VERSION 5.8 ;
BUSBITCHARS "[]" ;
DIVIDERCHAR "/" ;
UNITS
    DATABASE MICRONS 1000 ;
END UNITS

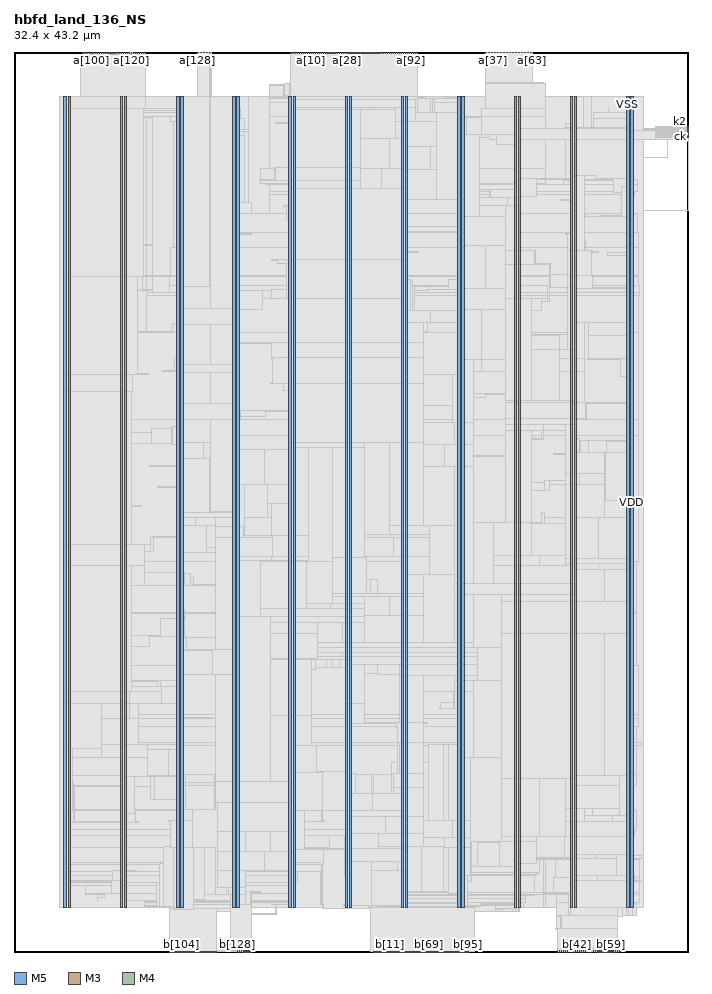
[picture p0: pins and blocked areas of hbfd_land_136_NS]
MACRO hbfd_land_136_NS
  FOREIGN hbfd_land_136_NS 0 0 ;
  CLASS BLOCK ;
  SIZE 32.4 BY 43.2 ;
  PIN a[0]
    DIRECTION INPUT ;
    USE SIGNAL ;
    PORT
      LAYER M5 ;
        RECT  13.296 43.116 13.32 43.2 ;
    END
  END a[0]
  PIN a[100]
    DIRECTION INPUT ;
    USE SIGNAL ;
    PORT
      LAYER M5 ;
        RECT  3.696 43.116 3.72 43.2 ;
    END
  END a[100]
  PIN a[101]
    DIRECTION INPUT ;
    USE SIGNAL ;
    PORT
      LAYER M5 ;
        RECT  3.792 43.116 3.816 43.2 ;
    END
  END a[101]
  PIN a[102]
    DIRECTION INPUT ;
    USE SIGNAL ;
    PORT
      LAYER M5 ;
        RECT  3.888 43.116 3.912 43.2 ;
    END
  END a[102]
  PIN a[103]
    DIRECTION INPUT ;
    USE SIGNAL ;
    PORT
      LAYER M5 ;
        RECT  3.984 43.116 4.008 43.2 ;
    END
  END a[103]
  PIN a[104]
    DIRECTION INPUT ;
    USE SIGNAL ;
    PORT
      LAYER M5 ;
        RECT  4.08 43.116 4.104 43.2 ;
    END
  END a[104]
  PIN a[105]
    DIRECTION INPUT ;
    USE SIGNAL ;
    PORT
      LAYER M5 ;
        RECT  4.176 43.116 4.2 43.2 ;
    END
  END a[105]
  PIN a[106]
    DIRECTION INPUT ;
    USE SIGNAL ;
    PORT
      LAYER M5 ;
        RECT  4.272 43.116 4.296 43.2 ;
    END
  END a[106]
  PIN a[107]
    DIRECTION INPUT ;
    USE SIGNAL ;
    PORT
      LAYER M5 ;
        RECT  4.368 43.116 4.392 43.2 ;
    END
  END a[107]
  PIN a[108]
    DIRECTION INPUT ;
    USE SIGNAL ;
    PORT
      LAYER M5 ;
        RECT  4.464 43.116 4.488 43.2 ;
    END
  END a[108]
  PIN a[109]
    DIRECTION INPUT ;
    USE SIGNAL ;
    PORT
      LAYER M5 ;
        RECT  4.56 43.116 4.584 43.2 ;
    END
  END a[109]
  PIN a[10]
    DIRECTION INPUT ;
    USE SIGNAL ;
    PORT
      LAYER M5 ;
        RECT  14.256 43.116 14.28 43.2 ;
    END
  END a[10]
  PIN a[110]
    DIRECTION INPUT ;
    USE SIGNAL ;
    PORT
      LAYER M5 ;
        RECT  4.656 43.116 4.68 43.2 ;
    END
  END a[110]
  PIN a[111]
    DIRECTION INPUT ;
    USE SIGNAL ;
    PORT
      LAYER M5 ;
        RECT  4.752 43.116 4.776 43.2 ;
    END
  END a[111]
  PIN a[112]
    DIRECTION INPUT ;
    USE SIGNAL ;
    PORT
      LAYER M5 ;
        RECT  4.848 43.116 4.872 43.2 ;
    END
  END a[112]
  PIN a[113]
    DIRECTION INPUT ;
    USE SIGNAL ;
    PORT
      LAYER M5 ;
        RECT  4.944 43.116 4.968 43.2 ;
    END
  END a[113]
  PIN a[114]
    DIRECTION INPUT ;
    USE SIGNAL ;
    PORT
      LAYER M5 ;
        RECT  5.04 43.116 5.064 43.2 ;
    END
  END a[114]
  PIN a[115]
    DIRECTION INPUT ;
    USE SIGNAL ;
    PORT
      LAYER M5 ;
        RECT  5.136 43.116 5.16 43.2 ;
    END
  END a[115]
  PIN a[116]
    DIRECTION INPUT ;
    USE SIGNAL ;
    PORT
      LAYER M5 ;
        RECT  5.232 43.116 5.256 43.2 ;
    END
  END a[116]
  PIN a[117]
    DIRECTION INPUT ;
    USE SIGNAL ;
    PORT
      LAYER M5 ;
        RECT  5.328 43.116 5.352 43.2 ;
    END
  END a[117]
  PIN a[118]
    DIRECTION INPUT ;
    USE SIGNAL ;
    PORT
      LAYER M5 ;
        RECT  5.424 43.116 5.448 43.2 ;
    END
  END a[118]
  PIN a[119]
    DIRECTION INPUT ;
    USE SIGNAL ;
    PORT
      LAYER M5 ;
        RECT  5.52 43.116 5.544 43.2 ;
    END
  END a[119]
  PIN a[11]
    DIRECTION INPUT ;
    USE SIGNAL ;
    PORT
      LAYER M5 ;
        RECT  14.352 43.116 14.376 43.2 ;
    END
  END a[11]
  PIN a[120]
    DIRECTION INPUT ;
    USE SIGNAL ;
    PORT
      LAYER M5 ;
        RECT  5.616 43.116 5.64 43.2 ;
    END
  END a[120]
  PIN a[121]
    DIRECTION INPUT ;
    USE SIGNAL ;
    PORT
      LAYER M5 ;
        RECT  5.712 43.116 5.736 43.2 ;
    END
  END a[121]
  PIN a[122]
    DIRECTION INPUT ;
    USE SIGNAL ;
    PORT
      LAYER M5 ;
        RECT  5.808 43.116 5.832 43.2 ;
    END
  END a[122]
  PIN a[123]
    DIRECTION INPUT ;
    USE SIGNAL ;
    PORT
      LAYER M5 ;
        RECT  5.904 43.116 5.928 43.2 ;
    END
  END a[123]
  PIN a[124]
    DIRECTION INPUT ;
    USE SIGNAL ;
    PORT
      LAYER M5 ;
        RECT  6 43.116 6.024 43.2 ;
    END
  END a[124]
  PIN a[125]
    DIRECTION INPUT ;
    USE SIGNAL ;
    PORT
      LAYER M5 ;
        RECT  6.096 43.116 6.12 43.2 ;
    END
  END a[125]
  PIN a[126]
    DIRECTION INPUT ;
    USE SIGNAL ;
    PORT
      LAYER M5 ;
        RECT  6.192 43.116 6.216 43.2 ;
    END
  END a[126]
  PIN a[127]
    DIRECTION INPUT ;
    USE SIGNAL ;
    PORT
      LAYER M5 ;
        RECT  6.288 43.116 6.312 43.2 ;
    END
  END a[127]
  PIN a[128]
    DIRECTION INPUT ;
    USE SIGNAL ;
    PORT
      LAYER M3 ;
        RECT  8.82 43.163 8.838 43.2 ;
    END
  END a[128]
  PIN a[129]
    DIRECTION INPUT ;
    USE SIGNAL ;
    PORT
      LAYER M3 ;
        RECT  8.892 43.163 8.91 43.2 ;
    END
  END a[129]
  PIN a[12]
    DIRECTION INPUT ;
    USE SIGNAL ;
    PORT
      LAYER M5 ;
        RECT  14.448 43.116 14.472 43.2 ;
    END
  END a[12]
  PIN a[130]
    DIRECTION INPUT ;
    USE SIGNAL ;
    PORT
      LAYER M3 ;
        RECT  8.964 43.163 8.982 43.2 ;
    END
  END a[130]
  PIN a[131]
    DIRECTION INPUT ;
    USE SIGNAL ;
    PORT
      LAYER M3 ;
        RECT  9.036 43.163 9.054 43.2 ;
    END
  END a[131]
  PIN a[132]
    DIRECTION INPUT ;
    USE SIGNAL ;
    PORT
      LAYER M3 ;
        RECT  9.108 43.163 9.126 43.2 ;
    END
  END a[132]
  PIN a[133]
    DIRECTION INPUT ;
    USE SIGNAL ;
    PORT
      LAYER M3 ;
        RECT  9.18 43.163 9.198 43.2 ;
    END
  END a[133]
  PIN a[134]
    DIRECTION INPUT ;
    USE SIGNAL ;
    PORT
      LAYER M3 ;
        RECT  9.252 43.163 9.27 43.2 ;
    END
  END a[134]
  PIN a[135]
    DIRECTION INPUT ;
    USE SIGNAL ;
    PORT
      LAYER M3 ;
        RECT  9.324 43.163 9.342 43.2 ;
    END
  END a[135]
  PIN a[13]
    DIRECTION INPUT ;
    USE SIGNAL ;
    PORT
      LAYER M5 ;
        RECT  14.544 43.116 14.568 43.2 ;
    END
  END a[13]
  PIN a[14]
    DIRECTION INPUT ;
    USE SIGNAL ;
    PORT
      LAYER M5 ;
        RECT  14.64 43.116 14.664 43.2 ;
    END
  END a[14]
  PIN a[15]
    DIRECTION INPUT ;
    USE SIGNAL ;
    PORT
      LAYER M5 ;
        RECT  14.736 43.116 14.76 43.2 ;
    END
  END a[15]
  PIN a[16]
    DIRECTION INPUT ;
    USE SIGNAL ;
    PORT
      LAYER M5 ;
        RECT  14.832 43.116 14.856 43.2 ;
    END
  END a[16]
  PIN a[17]
    DIRECTION INPUT ;
    USE SIGNAL ;
    PORT
      LAYER M5 ;
        RECT  14.928 43.116 14.952 43.2 ;
    END
  END a[17]
  PIN a[18]
    DIRECTION INPUT ;
    USE SIGNAL ;
    PORT
      LAYER M5 ;
        RECT  15.024 43.116 15.048 43.2 ;
    END
  END a[18]
  PIN a[19]
    DIRECTION INPUT ;
    USE SIGNAL ;
    PORT
      LAYER M5 ;
        RECT  15.12 43.116 15.144 43.2 ;
    END
  END a[19]
  PIN a[1]
    DIRECTION INPUT ;
    USE SIGNAL ;
    PORT
      LAYER M5 ;
        RECT  13.392 43.116 13.416 43.2 ;
    END
  END a[1]
  PIN a[20]
    DIRECTION INPUT ;
    USE SIGNAL ;
    PORT
      LAYER M5 ;
        RECT  15.216 43.116 15.24 43.2 ;
    END
  END a[20]
  PIN a[21]
    DIRECTION INPUT ;
    USE SIGNAL ;
    PORT
      LAYER M5 ;
        RECT  15.312 43.116 15.336 43.2 ;
    END
  END a[21]
  PIN a[22]
    DIRECTION INPUT ;
    USE SIGNAL ;
    PORT
      LAYER M5 ;
        RECT  15.408 43.116 15.432 43.2 ;
    END
  END a[22]
  PIN a[23]
    DIRECTION INPUT ;
    USE SIGNAL ;
    PORT
      LAYER M5 ;
        RECT  15.504 43.116 15.528 43.2 ;
    END
  END a[23]
  PIN a[24]
    DIRECTION INPUT ;
    USE SIGNAL ;
    PORT
      LAYER M5 ;
        RECT  15.6 43.116 15.624 43.2 ;
    END
  END a[24]
  PIN a[25]
    DIRECTION INPUT ;
    USE SIGNAL ;
    PORT
      LAYER M5 ;
        RECT  15.696 43.116 15.72 43.2 ;
    END
  END a[25]
  PIN a[26]
    DIRECTION INPUT ;
    USE SIGNAL ;
    PORT
      LAYER M5 ;
        RECT  15.792 43.116 15.816 43.2 ;
    END
  END a[26]
  PIN a[27]
    DIRECTION INPUT ;
    USE SIGNAL ;
    PORT
      LAYER M5 ;
        RECT  15.888 43.116 15.912 43.2 ;
    END
  END a[27]
  PIN a[28]
    DIRECTION INPUT ;
    USE SIGNAL ;
    PORT
      LAYER M5 ;
        RECT  15.984 43.116 16.008 43.2 ;
    END
  END a[28]
  PIN a[29]
    DIRECTION INPUT ;
    USE SIGNAL ;
    PORT
      LAYER M5 ;
        RECT  16.08 43.116 16.104 43.2 ;
    END
  END a[29]
  PIN a[2]
    DIRECTION INPUT ;
    USE SIGNAL ;
    PORT
      LAYER M5 ;
        RECT  13.488 43.116 13.512 43.2 ;
    END
  END a[2]
  PIN a[30]
    DIRECTION INPUT ;
    USE SIGNAL ;
    PORT
      LAYER M5 ;
        RECT  16.176 43.116 16.2 43.2 ;
    END
  END a[30]
  PIN a[31]
    DIRECTION INPUT ;
    USE SIGNAL ;
    PORT
      LAYER M5 ;
        RECT  16.272 43.116 16.296 43.2 ;
    END
  END a[31]
  PIN a[32]
    DIRECTION INPUT ;
    USE SIGNAL ;
    PORT
      LAYER M3 ;
        RECT  22.644 43.163 22.662 43.2 ;
    END
  END a[32]
  PIN a[33]
    DIRECTION INPUT ;
    USE SIGNAL ;
    PORT
      LAYER M3 ;
        RECT  22.716 43.163 22.734 43.2 ;
    END
  END a[33]
  PIN a[34]
    DIRECTION INPUT ;
    USE SIGNAL ;
    PORT
      LAYER M3 ;
        RECT  22.788 43.163 22.806 43.2 ;
    END
  END a[34]
  PIN a[35]
    DIRECTION INPUT ;
    USE SIGNAL ;
    PORT
      LAYER M3 ;
        RECT  22.86 43.163 22.878 43.2 ;
    END
  END a[35]
  PIN a[36]
    DIRECTION INPUT ;
    USE SIGNAL ;
    PORT
      LAYER M3 ;
        RECT  22.932 43.163 22.95 43.2 ;
    END
  END a[36]
  PIN a[37]
    DIRECTION INPUT ;
    USE SIGNAL ;
    PORT
      LAYER M3 ;
        RECT  23.004 43.163 23.022 43.2 ;
    END
  END a[37]
  PIN a[38]
    DIRECTION INPUT ;
    USE SIGNAL ;
    PORT
      LAYER M3 ;
        RECT  23.076 43.163 23.094 43.2 ;
    END
  END a[38]
  PIN a[39]
    DIRECTION INPUT ;
    USE SIGNAL ;
    PORT
      LAYER M3 ;
        RECT  23.148 43.163 23.166 43.2 ;
    END
  END a[39]
  PIN a[3]
    DIRECTION INPUT ;
    USE SIGNAL ;
    PORT
      LAYER M5 ;
        RECT  13.584 43.116 13.608 43.2 ;
    END
  END a[3]
  PIN a[40]
    DIRECTION INPUT ;
    USE SIGNAL ;
    PORT
      LAYER M3 ;
        RECT  23.22 43.163 23.238 43.2 ;
    END
  END a[40]
  PIN a[41]
    DIRECTION INPUT ;
    USE SIGNAL ;
    PORT
      LAYER M3 ;
        RECT  23.292 43.163 23.31 43.2 ;
    END
  END a[41]
  PIN a[42]
    DIRECTION INPUT ;
    USE SIGNAL ;
    PORT
      LAYER M3 ;
        RECT  23.364 43.163 23.382 43.2 ;
    END
  END a[42]
  PIN a[43]
    DIRECTION INPUT ;
    USE SIGNAL ;
    PORT
      LAYER M3 ;
        RECT  23.436 43.163 23.454 43.2 ;
    END
  END a[43]
  PIN a[44]
    DIRECTION INPUT ;
    USE SIGNAL ;
    PORT
      LAYER M3 ;
        RECT  23.508 43.163 23.526 43.2 ;
    END
  END a[44]
  PIN a[45]
    DIRECTION INPUT ;
    USE SIGNAL ;
    PORT
      LAYER M3 ;
        RECT  23.58 43.163 23.598 43.2 ;
    END
  END a[45]
  PIN a[46]
    DIRECTION INPUT ;
    USE SIGNAL ;
    PORT
      LAYER M3 ;
        RECT  23.652 43.163 23.67 43.2 ;
    END
  END a[46]
  PIN a[47]
    DIRECTION INPUT ;
    USE SIGNAL ;
    PORT
      LAYER M3 ;
        RECT  23.724 43.163 23.742 43.2 ;
    END
  END a[47]
  PIN a[48]
    DIRECTION INPUT ;
    USE SIGNAL ;
    PORT
      LAYER M3 ;
        RECT  23.796 43.163 23.814 43.2 ;
    END
  END a[48]
  PIN a[49]
    DIRECTION INPUT ;
    USE SIGNAL ;
    PORT
      LAYER M3 ;
        RECT  23.868 43.163 23.886 43.2 ;
    END
  END a[49]
  PIN a[4]
    DIRECTION INPUT ;
    USE SIGNAL ;
    PORT
      LAYER M5 ;
        RECT  13.68 43.116 13.704 43.2 ;
    END
  END a[4]
  PIN a[50]
    DIRECTION INPUT ;
    USE SIGNAL ;
    PORT
      LAYER M3 ;
        RECT  23.94 43.163 23.958 43.2 ;
    END
  END a[50]
  PIN a[51]
    DIRECTION INPUT ;
    USE SIGNAL ;
    PORT
      LAYER M3 ;
        RECT  24.012 43.163 24.03 43.2 ;
    END
  END a[51]
  PIN a[52]
    DIRECTION INPUT ;
    USE SIGNAL ;
    PORT
      LAYER M3 ;
        RECT  24.084 43.163 24.102 43.2 ;
    END
  END a[52]
  PIN a[53]
    DIRECTION INPUT ;
    USE SIGNAL ;
    PORT
      LAYER M3 ;
        RECT  24.156 43.163 24.174 43.2 ;
    END
  END a[53]
  PIN a[54]
    DIRECTION INPUT ;
    USE SIGNAL ;
    PORT
      LAYER M3 ;
        RECT  24.228 43.163 24.246 43.2 ;
    END
  END a[54]
  PIN a[55]
    DIRECTION INPUT ;
    USE SIGNAL ;
    PORT
      LAYER M3 ;
        RECT  24.3 43.163 24.318 43.2 ;
    END
  END a[55]
  PIN a[56]
    DIRECTION INPUT ;
    USE SIGNAL ;
    PORT
      LAYER M3 ;
        RECT  24.372 43.163 24.39 43.2 ;
    END
  END a[56]
  PIN a[57]
    DIRECTION INPUT ;
    USE SIGNAL ;
    PORT
      LAYER M3 ;
        RECT  24.444 43.163 24.462 43.2 ;
    END
  END a[57]
  PIN a[58]
    DIRECTION INPUT ;
    USE SIGNAL ;
    PORT
      LAYER M3 ;
        RECT  24.516 43.163 24.534 43.2 ;
    END
  END a[58]
  PIN a[59]
    DIRECTION INPUT ;
    USE SIGNAL ;
    PORT
      LAYER M3 ;
        RECT  24.588 43.163 24.606 43.2 ;
    END
  END a[59]
  PIN a[5]
    DIRECTION INPUT ;
    USE SIGNAL ;
    PORT
      LAYER M5 ;
        RECT  13.776 43.116 13.8 43.2 ;
    END
  END a[5]
  PIN a[60]
    DIRECTION INPUT ;
    USE SIGNAL ;
    PORT
      LAYER M3 ;
        RECT  24.66 43.163 24.678 43.2 ;
    END
  END a[60]
  PIN a[61]
    DIRECTION INPUT ;
    USE SIGNAL ;
    PORT
      LAYER M3 ;
        RECT  24.732 43.163 24.75 43.2 ;
    END
  END a[61]
  PIN a[62]
    DIRECTION INPUT ;
    USE SIGNAL ;
    PORT
      LAYER M3 ;
        RECT  24.804 43.163 24.822 43.2 ;
    END
  END a[62]
  PIN a[63]
    DIRECTION INPUT ;
    USE SIGNAL ;
    PORT
      LAYER M3 ;
        RECT  24.876 43.163 24.894 43.2 ;
    END
  END a[63]
  PIN a[64]
    DIRECTION INPUT ;
    USE SIGNAL ;
    PORT
      LAYER M5 ;
        RECT  16.368 43.116 16.392 43.2 ;
    END
  END a[64]
  PIN a[65]
    DIRECTION INPUT ;
    USE SIGNAL ;
    PORT
      LAYER M5 ;
        RECT  16.464 43.116 16.488 43.2 ;
    END
  END a[65]
  PIN a[66]
    DIRECTION INPUT ;
    USE SIGNAL ;
    PORT
      LAYER M5 ;
        RECT  16.56 43.116 16.584 43.2 ;
    END
  END a[66]
  PIN a[67]
    DIRECTION INPUT ;
    USE SIGNAL ;
    PORT
      LAYER M5 ;
        RECT  16.656 43.116 16.68 43.2 ;
    END
  END a[67]
  PIN a[68]
    DIRECTION INPUT ;
    USE SIGNAL ;
    PORT
      LAYER M5 ;
        RECT  16.752 43.116 16.776 43.2 ;
    END
  END a[68]
  PIN a[69]
    DIRECTION INPUT ;
    USE SIGNAL ;
    PORT
      LAYER M5 ;
        RECT  16.848 43.116 16.872 43.2 ;
    END
  END a[69]
  PIN a[6]
    DIRECTION INPUT ;
    USE SIGNAL ;
    PORT
      LAYER M5 ;
        RECT  13.872 43.116 13.896 43.2 ;
    END
  END a[6]
  PIN a[70]
    DIRECTION INPUT ;
    USE SIGNAL ;
    PORT
      LAYER M5 ;
        RECT  16.944 43.116 16.968 43.2 ;
    END
  END a[70]
  PIN a[71]
    DIRECTION INPUT ;
    USE SIGNAL ;
    PORT
      LAYER M5 ;
        RECT  17.04 43.116 17.064 43.2 ;
    END
  END a[71]
  PIN a[72]
    DIRECTION INPUT ;
    USE SIGNAL ;
    PORT
      LAYER M5 ;
        RECT  17.136 43.116 17.16 43.2 ;
    END
  END a[72]
  PIN a[73]
    DIRECTION INPUT ;
    USE SIGNAL ;
    PORT
      LAYER M5 ;
        RECT  17.232 43.116 17.256 43.2 ;
    END
  END a[73]
  PIN a[74]
    DIRECTION INPUT ;
    USE SIGNAL ;
    PORT
      LAYER M5 ;
        RECT  17.328 43.116 17.352 43.2 ;
    END
  END a[74]
  PIN a[75]
    DIRECTION INPUT ;
    USE SIGNAL ;
    PORT
      LAYER M5 ;
        RECT  17.424 43.116 17.448 43.2 ;
    END
  END a[75]
  PIN a[76]
    DIRECTION INPUT ;
    USE SIGNAL ;
    PORT
      LAYER M5 ;
        RECT  17.52 43.116 17.544 43.2 ;
    END
  END a[76]
  PIN a[77]
    DIRECTION INPUT ;
    USE SIGNAL ;
    PORT
      LAYER M5 ;
        RECT  17.616 43.116 17.64 43.2 ;
    END
  END a[77]
  PIN a[78]
    DIRECTION INPUT ;
    USE SIGNAL ;
    PORT
      LAYER M5 ;
        RECT  17.712 43.116 17.736 43.2 ;
    END
  END a[78]
  PIN a[79]
    DIRECTION INPUT ;
    USE SIGNAL ;
    PORT
      LAYER M5 ;
        RECT  17.808 43.116 17.832 43.2 ;
    END
  END a[79]
  PIN a[7]
    DIRECTION INPUT ;
    USE SIGNAL ;
    PORT
      LAYER M5 ;
        RECT  13.968 43.116 13.992 43.2 ;
    END
  END a[7]
  PIN a[80]
    DIRECTION INPUT ;
    USE SIGNAL ;
    PORT
      LAYER M5 ;
        RECT  17.904 43.116 17.928 43.2 ;
    END
  END a[80]
  PIN a[81]
    DIRECTION INPUT ;
    USE SIGNAL ;
    PORT
      LAYER M5 ;
        RECT  18 43.116 18.024 43.2 ;
    END
  END a[81]
  PIN a[82]
    DIRECTION INPUT ;
    USE SIGNAL ;
    PORT
      LAYER M5 ;
        RECT  18.096 43.116 18.12 43.2 ;
    END
  END a[82]
  PIN a[83]
    DIRECTION INPUT ;
    USE SIGNAL ;
    PORT
      LAYER M5 ;
        RECT  18.192 43.116 18.216 43.2 ;
    END
  END a[83]
  PIN a[84]
    DIRECTION INPUT ;
    USE SIGNAL ;
    PORT
      LAYER M5 ;
        RECT  18.288 43.116 18.312 43.2 ;
    END
  END a[84]
  PIN a[85]
    DIRECTION INPUT ;
    USE SIGNAL ;
    PORT
      LAYER M5 ;
        RECT  18.384 43.116 18.408 43.2 ;
    END
  END a[85]
  PIN a[86]
    DIRECTION INPUT ;
    USE SIGNAL ;
    PORT
      LAYER M5 ;
        RECT  18.48 43.116 18.504 43.2 ;
    END
  END a[86]
  PIN a[87]
    DIRECTION INPUT ;
    USE SIGNAL ;
    PORT
      LAYER M5 ;
        RECT  18.576 43.116 18.6 43.2 ;
    END
  END a[87]
  PIN a[88]
    DIRECTION INPUT ;
    USE SIGNAL ;
    PORT
      LAYER M5 ;
        RECT  18.672 43.116 18.696 43.2 ;
    END
  END a[88]
  PIN a[89]
    DIRECTION INPUT ;
    USE SIGNAL ;
    PORT
      LAYER M5 ;
        RECT  18.768 43.116 18.792 43.2 ;
    END
  END a[89]
  PIN a[8]
    DIRECTION INPUT ;
    USE SIGNAL ;
    PORT
      LAYER M5 ;
        RECT  14.064 43.116 14.088 43.2 ;
    END
  END a[8]
  PIN a[90]
    DIRECTION INPUT ;
    USE SIGNAL ;
    PORT
      LAYER M5 ;
        RECT  18.864 43.116 18.888 43.2 ;
    END
  END a[90]
  PIN a[91]
    DIRECTION INPUT ;
    USE SIGNAL ;
    PORT
      LAYER M5 ;
        RECT  18.96 43.116 18.984 43.2 ;
    END
  END a[91]
  PIN a[92]
    DIRECTION INPUT ;
    USE SIGNAL ;
    PORT
      LAYER M5 ;
        RECT  19.056 43.116 19.08 43.2 ;
    END
  END a[92]
  PIN a[93]
    DIRECTION INPUT ;
    USE SIGNAL ;
    PORT
      LAYER M5 ;
        RECT  19.152 43.116 19.176 43.2 ;
    END
  END a[93]
  PIN a[94]
    DIRECTION INPUT ;
    USE SIGNAL ;
    PORT
      LAYER M5 ;
        RECT  19.248 43.116 19.272 43.2 ;
    END
  END a[94]
  PIN a[95]
    DIRECTION INPUT ;
    USE SIGNAL ;
    PORT
      LAYER M5 ;
        RECT  19.344 43.116 19.368 43.2 ;
    END
  END a[95]
  PIN a[96]
    DIRECTION INPUT ;
    USE SIGNAL ;
    PORT
      LAYER M5 ;
        RECT  3.312 43.116 3.336 43.2 ;
    END
  END a[96]
  PIN a[97]
    DIRECTION INPUT ;
    USE SIGNAL ;
    PORT
      LAYER M5 ;
        RECT  3.408 43.116 3.432 43.2 ;
    END
  END a[97]
  PIN a[98]
    DIRECTION INPUT ;
    USE SIGNAL ;
    PORT
      LAYER M5 ;
        RECT  3.504 43.116 3.528 43.2 ;
    END
  END a[98]
  PIN a[99]
    DIRECTION INPUT ;
    USE SIGNAL ;
    PORT
      LAYER M5 ;
        RECT  3.6 43.116 3.624 43.2 ;
    END
  END a[99]
  PIN a[9]
    DIRECTION INPUT ;
    USE SIGNAL ;
    PORT
      LAYER M5 ;
        RECT  14.16 43.116 14.184 43.2 ;
    END
  END a[9]
  PIN b[0]
    DIRECTION OUTPUT ;
    USE SIGNAL ;
    PORT
      LAYER M3 ;
        RECT  17.244 0 17.262 0.037 ;
    END
  END b[0]
  PIN b[100]
    DIRECTION OUTPUT ;
    USE SIGNAL ;
    PORT
      LAYER M3 ;
        RECT  7.74 0 7.758 0.037 ;
    END
  END b[100]
  PIN b[101]
    DIRECTION OUTPUT ;
    USE SIGNAL ;
    PORT
      LAYER M3 ;
        RECT  7.812 0 7.83 0.037 ;
    END
  END b[101]
  PIN b[102]
    DIRECTION OUTPUT ;
    USE SIGNAL ;
    PORT
      LAYER M3 ;
        RECT  7.884 0 7.902 0.037 ;
    END
  END b[102]
  PIN b[103]
    DIRECTION OUTPUT ;
    USE SIGNAL ;
    PORT
      LAYER M3 ;
        RECT  7.956 0 7.974 0.037 ;
    END
  END b[103]
  PIN b[104]
    DIRECTION OUTPUT ;
    USE SIGNAL ;
    PORT
      LAYER M3 ;
        RECT  8.028 0 8.046 0.037 ;
    END
  END b[104]
  PIN b[105]
    DIRECTION OUTPUT ;
    USE SIGNAL ;
    PORT
      LAYER M3 ;
        RECT  8.1 0 8.118 0.037 ;
    END
  END b[105]
  PIN b[106]
    DIRECTION OUTPUT ;
    USE SIGNAL ;
    PORT
      LAYER M3 ;
        RECT  8.172 0 8.19 0.037 ;
    END
  END b[106]
  PIN b[107]
    DIRECTION OUTPUT ;
    USE SIGNAL ;
    PORT
      LAYER M3 ;
        RECT  8.244 0 8.262 0.037 ;
    END
  END b[107]
  PIN b[108]
    DIRECTION OUTPUT ;
    USE SIGNAL ;
    PORT
      LAYER M3 ;
        RECT  8.316 0 8.334 0.037 ;
    END
  END b[108]
  PIN b[109]
    DIRECTION OUTPUT ;
    USE SIGNAL ;
    PORT
      LAYER M3 ;
        RECT  8.388 0 8.406 0.037 ;
    END
  END b[109]
  PIN b[10]
    DIRECTION OUTPUT ;
    USE SIGNAL ;
    PORT
      LAYER M3 ;
        RECT  17.964 0 17.982 0.037 ;
    END
  END b[10]
  PIN b[110]
    DIRECTION OUTPUT ;
    USE SIGNAL ;
    PORT
      LAYER M3 ;
        RECT  8.46 0 8.478 0.037 ;
    END
  END b[110]
  PIN b[111]
    DIRECTION OUTPUT ;
    USE SIGNAL ;
    PORT
      LAYER M3 ;
        RECT  8.532 0 8.55 0.037 ;
    END
  END b[111]
  PIN b[112]
    DIRECTION OUTPUT ;
    USE SIGNAL ;
    PORT
      LAYER M3 ;
        RECT  8.604 0 8.622 0.037 ;
    END
  END b[112]
  PIN b[113]
    DIRECTION OUTPUT ;
    USE SIGNAL ;
    PORT
      LAYER M3 ;
        RECT  8.676 0 8.694 0.037 ;
    END
  END b[113]
  PIN b[114]
    DIRECTION OUTPUT ;
    USE SIGNAL ;
    PORT
      LAYER M3 ;
        RECT  8.748 0 8.766 0.037 ;
    END
  END b[114]
  PIN b[115]
    DIRECTION OUTPUT ;
    USE SIGNAL ;
    PORT
      LAYER M3 ;
        RECT  8.82 0 8.838 0.037 ;
    END
  END b[115]
  PIN b[116]
    DIRECTION OUTPUT ;
    USE SIGNAL ;
    PORT
      LAYER M3 ;
        RECT  8.892 0 8.91 0.037 ;
    END
  END b[116]
  PIN b[117]
    DIRECTION OUTPUT ;
    USE SIGNAL ;
    PORT
      LAYER M3 ;
        RECT  8.964 0 8.982 0.037 ;
    END
  END b[117]
  PIN b[118]
    DIRECTION OUTPUT ;
    USE SIGNAL ;
    PORT
      LAYER M3 ;
        RECT  9.036 0 9.054 0.037 ;
    END
  END b[118]
  PIN b[119]
    DIRECTION OUTPUT ;
    USE SIGNAL ;
    PORT
      LAYER M3 ;
        RECT  9.108 0 9.126 0.037 ;
    END
  END b[119]
  PIN b[11]
    DIRECTION OUTPUT ;
    USE SIGNAL ;
    PORT
      LAYER M3 ;
        RECT  18.036 0 18.054 0.037 ;
    END
  END b[11]
  PIN b[120]
    DIRECTION OUTPUT ;
    USE SIGNAL ;
    PORT
      LAYER M3 ;
        RECT  9.18 0 9.198 0.037 ;
    END
  END b[120]
  PIN b[121]
    DIRECTION OUTPUT ;
    USE SIGNAL ;
    PORT
      LAYER M3 ;
        RECT  9.252 0 9.27 0.037 ;
    END
  END b[121]
  PIN b[122]
    DIRECTION OUTPUT ;
    USE SIGNAL ;
    PORT
      LAYER M3 ;
        RECT  9.324 0 9.342 0.037 ;
    END
  END b[122]
  PIN b[123]
    DIRECTION OUTPUT ;
    USE SIGNAL ;
    PORT
      LAYER M3 ;
        RECT  9.396 0 9.414 0.037 ;
    END
  END b[123]
  PIN b[124]
    DIRECTION OUTPUT ;
    USE SIGNAL ;
    PORT
      LAYER M3 ;
        RECT  9.468 0 9.486 0.037 ;
    END
  END b[124]
  PIN b[125]
    DIRECTION OUTPUT ;
    USE SIGNAL ;
    PORT
      LAYER M3 ;
        RECT  9.54 0 9.558 0.037 ;
    END
  END b[125]
  PIN b[126]
    DIRECTION OUTPUT ;
    USE SIGNAL ;
    PORT
      LAYER M3 ;
        RECT  9.612 0 9.63 0.037 ;
    END
  END b[126]
  PIN b[127]
    DIRECTION OUTPUT ;
    USE SIGNAL ;
    PORT
      LAYER M3 ;
        RECT  9.684 0 9.702 0.037 ;
    END
  END b[127]
  PIN b[128]
    DIRECTION OUTPUT ;
    USE SIGNAL ;
    PORT
      LAYER M5 ;
        RECT  10.704 0 10.728 0.084 ;
    END
  END b[128]
  PIN b[129]
    DIRECTION OUTPUT ;
    USE SIGNAL ;
    PORT
      LAYER M5 ;
        RECT  10.8 0 10.824 0.084 ;
    END
  END b[129]
  PIN b[12]
    DIRECTION OUTPUT ;
    USE SIGNAL ;
    PORT
      LAYER M3 ;
        RECT  18.108 0 18.126 0.037 ;
    END
  END b[12]
  PIN b[130]
    DIRECTION OUTPUT ;
    USE SIGNAL ;
    PORT
      LAYER M5 ;
        RECT  10.896 0 10.92 0.084 ;
    END
  END b[130]
  PIN b[131]
    DIRECTION OUTPUT ;
    USE SIGNAL ;
    PORT
      LAYER M5 ;
        RECT  10.992 0 11.016 0.084 ;
    END
  END b[131]
  PIN b[132]
    DIRECTION OUTPUT ;
    USE SIGNAL ;
    PORT
      LAYER M5 ;
        RECT  11.088 0 11.112 0.084 ;
    END
  END b[132]
  PIN b[133]
    DIRECTION OUTPUT ;
    USE SIGNAL ;
    PORT
      LAYER M5 ;
        RECT  11.184 0 11.208 0.084 ;
    END
  END b[133]
  PIN b[134]
    DIRECTION OUTPUT ;
    USE SIGNAL ;
    PORT
      LAYER M5 ;
        RECT  11.28 0 11.304 0.084 ;
    END
  END b[134]
  PIN b[135]
    DIRECTION OUTPUT ;
    USE SIGNAL ;
    PORT
      LAYER M5 ;
        RECT  11.376 0 11.4 0.084 ;
    END
  END b[135]
  PIN b[13]
    DIRECTION OUTPUT ;
    USE SIGNAL ;
    PORT
      LAYER M3 ;
        RECT  18.18 0 18.198 0.037 ;
    END
  END b[13]
  PIN b[14]
    DIRECTION OUTPUT ;
    USE SIGNAL ;
    PORT
      LAYER M3 ;
        RECT  18.252 0 18.27 0.037 ;
    END
  END b[14]
  PIN b[15]
    DIRECTION OUTPUT ;
    USE SIGNAL ;
    PORT
      LAYER M3 ;
        RECT  18.324 0 18.342 0.037 ;
    END
  END b[15]
  PIN b[16]
    DIRECTION OUTPUT ;
    USE SIGNAL ;
    PORT
      LAYER M3 ;
        RECT  18.396 0 18.414 0.037 ;
    END
  END b[16]
  PIN b[17]
    DIRECTION OUTPUT ;
    USE SIGNAL ;
    PORT
      LAYER M3 ;
        RECT  18.468 0 18.486 0.037 ;
    END
  END b[17]
  PIN b[18]
    DIRECTION OUTPUT ;
    USE SIGNAL ;
    PORT
      LAYER M3 ;
        RECT  18.54 0 18.558 0.037 ;
    END
  END b[18]
  PIN b[19]
    DIRECTION OUTPUT ;
    USE SIGNAL ;
    PORT
      LAYER M3 ;
        RECT  18.612 0 18.63 0.037 ;
    END
  END b[19]
  PIN b[1]
    DIRECTION OUTPUT ;
    USE SIGNAL ;
    PORT
      LAYER M3 ;
        RECT  17.316 0 17.334 0.037 ;
    END
  END b[1]
  PIN b[20]
    DIRECTION OUTPUT ;
    USE SIGNAL ;
    PORT
      LAYER M3 ;
        RECT  18.684 0 18.702 0.037 ;
    END
  END b[20]
  PIN b[21]
    DIRECTION OUTPUT ;
    USE SIGNAL ;
    PORT
      LAYER M3 ;
        RECT  18.756 0 18.774 0.037 ;
    END
  END b[21]
  PIN b[22]
    DIRECTION OUTPUT ;
    USE SIGNAL ;
    PORT
      LAYER M3 ;
        RECT  18.828 0 18.846 0.037 ;
    END
  END b[22]
  PIN b[23]
    DIRECTION OUTPUT ;
    USE SIGNAL ;
    PORT
      LAYER M3 ;
        RECT  18.9 0 18.918 0.037 ;
    END
  END b[23]
  PIN b[24]
    DIRECTION OUTPUT ;
    USE SIGNAL ;
    PORT
      LAYER M3 ;
        RECT  18.972 0 18.99 0.037 ;
    END
  END b[24]
  PIN b[25]
    DIRECTION OUTPUT ;
    USE SIGNAL ;
    PORT
      LAYER M3 ;
        RECT  19.044 0 19.062 0.037 ;
    END
  END b[25]
  PIN b[26]
    DIRECTION OUTPUT ;
    USE SIGNAL ;
    PORT
      LAYER M3 ;
        RECT  19.116 0 19.134 0.037 ;
    END
  END b[26]
  PIN b[27]
    DIRECTION OUTPUT ;
    USE SIGNAL ;
    PORT
      LAYER M3 ;
        RECT  19.188 0 19.206 0.037 ;
    END
  END b[27]
  PIN b[28]
    DIRECTION OUTPUT ;
    USE SIGNAL ;
    PORT
      LAYER M3 ;
        RECT  19.26 0 19.278 0.037 ;
    END
  END b[28]
  PIN b[29]
    DIRECTION OUTPUT ;
    USE SIGNAL ;
    PORT
      LAYER M3 ;
        RECT  19.332 0 19.35 0.037 ;
    END
  END b[29]
  PIN b[2]
    DIRECTION OUTPUT ;
    USE SIGNAL ;
    PORT
      LAYER M3 ;
        RECT  17.388 0 17.406 0.037 ;
    END
  END b[2]
  PIN b[30]
    DIRECTION OUTPUT ;
    USE SIGNAL ;
    PORT
      LAYER M3 ;
        RECT  19.404 0 19.422 0.037 ;
    END
  END b[30]
  PIN b[31]
    DIRECTION OUTPUT ;
    USE SIGNAL ;
    PORT
      LAYER M3 ;
        RECT  19.476 0 19.494 0.037 ;
    END
  END b[31]
  PIN b[32]
    DIRECTION OUTPUT ;
    USE SIGNAL ;
    PORT
      LAYER M5 ;
        RECT  26.064 0 26.088 0.084 ;
    END
  END b[32]
  PIN b[33]
    DIRECTION OUTPUT ;
    USE SIGNAL ;
    PORT
      LAYER M5 ;
        RECT  26.16 0 26.184 0.084 ;
    END
  END b[33]
  PIN b[34]
    DIRECTION OUTPUT ;
    USE SIGNAL ;
    PORT
      LAYER M5 ;
        RECT  26.256 0 26.28 0.084 ;
    END
  END b[34]
  PIN b[35]
    DIRECTION OUTPUT ;
    USE SIGNAL ;
    PORT
      LAYER M5 ;
        RECT  26.352 0 26.376 0.084 ;
    END
  END b[35]
  PIN b[36]
    DIRECTION OUTPUT ;
    USE SIGNAL ;
    PORT
      LAYER M5 ;
        RECT  26.448 0 26.472 0.084 ;
    END
  END b[36]
  PIN b[37]
    DIRECTION OUTPUT ;
    USE SIGNAL ;
    PORT
      LAYER M5 ;
        RECT  26.544 0 26.568 0.084 ;
    END
  END b[37]
  PIN b[38]
    DIRECTION OUTPUT ;
    USE SIGNAL ;
    PORT
      LAYER M5 ;
        RECT  26.64 0 26.664 0.084 ;
    END
  END b[38]
  PIN b[39]
    DIRECTION OUTPUT ;
    USE SIGNAL ;
    PORT
      LAYER M5 ;
        RECT  26.736 0 26.76 0.084 ;
    END
  END b[39]
  PIN b[3]
    DIRECTION OUTPUT ;
    USE SIGNAL ;
    PORT
      LAYER M3 ;
        RECT  17.46 0 17.478 0.037 ;
    END
  END b[3]
  PIN b[40]
    DIRECTION OUTPUT ;
    USE SIGNAL ;
    PORT
      LAYER M5 ;
        RECT  26.832 0 26.856 0.084 ;
    END
  END b[40]
  PIN b[41]
    DIRECTION OUTPUT ;
    USE SIGNAL ;
    PORT
      LAYER M5 ;
        RECT  26.928 0 26.952 0.084 ;
    END
  END b[41]
  PIN b[42]
    DIRECTION OUTPUT ;
    USE SIGNAL ;
    PORT
      LAYER M5 ;
        RECT  27.024 0 27.048 0.084 ;
    END
  END b[42]
  PIN b[43]
    DIRECTION OUTPUT ;
    USE SIGNAL ;
    PORT
      LAYER M5 ;
        RECT  27.12 0 27.144 0.084 ;
    END
  END b[43]
  PIN b[44]
    DIRECTION OUTPUT ;
    USE SIGNAL ;
    PORT
      LAYER M5 ;
        RECT  27.216 0 27.24 0.084 ;
    END
  END b[44]
  PIN b[45]
    DIRECTION OUTPUT ;
    USE SIGNAL ;
    PORT
      LAYER M5 ;
        RECT  27.312 0 27.336 0.084 ;
    END
  END b[45]
  PIN b[46]
    DIRECTION OUTPUT ;
    USE SIGNAL ;
    PORT
      LAYER M5 ;
        RECT  27.408 0 27.432 0.084 ;
    END
  END b[46]
  PIN b[47]
    DIRECTION OUTPUT ;
    USE SIGNAL ;
    PORT
      LAYER M5 ;
        RECT  27.504 0 27.528 0.084 ;
    END
  END b[47]
  PIN b[48]
    DIRECTION OUTPUT ;
    USE SIGNAL ;
    PORT
      LAYER M5 ;
        RECT  27.6 0 27.624 0.084 ;
    END
  END b[48]
  PIN b[49]
    DIRECTION OUTPUT ;
    USE SIGNAL ;
    PORT
      LAYER M5 ;
        RECT  27.696 0 27.72 0.084 ;
    END
  END b[49]
  PIN b[4]
    DIRECTION OUTPUT ;
    USE SIGNAL ;
    PORT
      LAYER M3 ;
        RECT  17.532 0 17.55 0.037 ;
    END
  END b[4]
  PIN b[50]
    DIRECTION OUTPUT ;
    USE SIGNAL ;
    PORT
      LAYER M5 ;
        RECT  27.792 0 27.816 0.084 ;
    END
  END b[50]
  PIN b[51]
    DIRECTION OUTPUT ;
    USE SIGNAL ;
    PORT
      LAYER M5 ;
        RECT  27.888 0 27.912 0.084 ;
    END
  END b[51]
  PIN b[52]
    DIRECTION OUTPUT ;
    USE SIGNAL ;
    PORT
      LAYER M5 ;
        RECT  27.984 0 28.008 0.084 ;
    END
  END b[52]
  PIN b[53]
    DIRECTION OUTPUT ;
    USE SIGNAL ;
    PORT
      LAYER M5 ;
        RECT  28.08 0 28.104 0.084 ;
    END
  END b[53]
  PIN b[54]
    DIRECTION OUTPUT ;
    USE SIGNAL ;
    PORT
      LAYER M5 ;
        RECT  28.176 0 28.2 0.084 ;
    END
  END b[54]
  PIN b[55]
    DIRECTION OUTPUT ;
    USE SIGNAL ;
    PORT
      LAYER M5 ;
        RECT  28.272 0 28.296 0.084 ;
    END
  END b[55]
  PIN b[56]
    DIRECTION OUTPUT ;
    USE SIGNAL ;
    PORT
      LAYER M5 ;
        RECT  28.368 0 28.392 0.084 ;
    END
  END b[56]
  PIN b[57]
    DIRECTION OUTPUT ;
    USE SIGNAL ;
    PORT
      LAYER M5 ;
        RECT  28.464 0 28.488 0.084 ;
    END
  END b[57]
  PIN b[58]
    DIRECTION OUTPUT ;
    USE SIGNAL ;
    PORT
      LAYER M5 ;
        RECT  28.56 0 28.584 0.084 ;
    END
  END b[58]
  PIN b[59]
    DIRECTION OUTPUT ;
    USE SIGNAL ;
    PORT
      LAYER M5 ;
        RECT  28.656 0 28.68 0.084 ;
    END
  END b[59]
  PIN b[5]
    DIRECTION OUTPUT ;
    USE SIGNAL ;
    PORT
      LAYER M3 ;
        RECT  17.604 0 17.622 0.037 ;
    END
  END b[5]
  PIN b[60]
    DIRECTION OUTPUT ;
    USE SIGNAL ;
    PORT
      LAYER M5 ;
        RECT  28.752 0 28.776 0.084 ;
    END
  END b[60]
  PIN b[61]
    DIRECTION OUTPUT ;
    USE SIGNAL ;
    PORT
      LAYER M5 ;
        RECT  28.848 0 28.872 0.084 ;
    END
  END b[61]
  PIN b[62]
    DIRECTION OUTPUT ;
    USE SIGNAL ;
    PORT
      LAYER M5 ;
        RECT  28.944 0 28.968 0.084 ;
    END
  END b[62]
  PIN b[63]
    DIRECTION OUTPUT ;
    USE SIGNAL ;
    PORT
      LAYER M5 ;
        RECT  29.04 0 29.064 0.084 ;
    END
  END b[63]
  PIN b[64]
    DIRECTION OUTPUT ;
    USE SIGNAL ;
    PORT
      LAYER M3 ;
        RECT  19.548 0 19.566 0.037 ;
    END
  END b[64]
  PIN b[65]
    DIRECTION OUTPUT ;
    USE SIGNAL ;
    PORT
      LAYER M3 ;
        RECT  19.62 0 19.638 0.037 ;
    END
  END b[65]
  PIN b[66]
    DIRECTION OUTPUT ;
    USE SIGNAL ;
    PORT
      LAYER M3 ;
        RECT  19.692 0 19.71 0.037 ;
    END
  END b[66]
  PIN b[67]
    DIRECTION OUTPUT ;
    USE SIGNAL ;
    PORT
      LAYER M3 ;
        RECT  19.764 0 19.782 0.037 ;
    END
  END b[67]
  PIN b[68]
    DIRECTION OUTPUT ;
    USE SIGNAL ;
    PORT
      LAYER M3 ;
        RECT  19.836 0 19.854 0.037 ;
    END
  END b[68]
  PIN b[69]
    DIRECTION OUTPUT ;
    USE SIGNAL ;
    PORT
      LAYER M3 ;
        RECT  19.908 0 19.926 0.037 ;
    END
  END b[69]
  PIN b[6]
    DIRECTION OUTPUT ;
    USE SIGNAL ;
    PORT
      LAYER M3 ;
        RECT  17.676 0 17.694 0.037 ;
    END
  END b[6]
  PIN b[70]
    DIRECTION OUTPUT ;
    USE SIGNAL ;
    PORT
      LAYER M3 ;
        RECT  19.98 0 19.998 0.037 ;
    END
  END b[70]
  PIN b[71]
    DIRECTION OUTPUT ;
    USE SIGNAL ;
    PORT
      LAYER M3 ;
        RECT  20.052 0 20.07 0.037 ;
    END
  END b[71]
  PIN b[72]
    DIRECTION OUTPUT ;
    USE SIGNAL ;
    PORT
      LAYER M3 ;
        RECT  20.124 0 20.142 0.037 ;
    END
  END b[72]
  PIN b[73]
    DIRECTION OUTPUT ;
    USE SIGNAL ;
    PORT
      LAYER M3 ;
        RECT  20.196 0 20.214 0.037 ;
    END
  END b[73]
  PIN b[74]
    DIRECTION OUTPUT ;
    USE SIGNAL ;
    PORT
      LAYER M3 ;
        RECT  20.268 0 20.286 0.037 ;
    END
  END b[74]
  PIN b[75]
    DIRECTION OUTPUT ;
    USE SIGNAL ;
    PORT
      LAYER M3 ;
        RECT  20.34 0 20.358 0.037 ;
    END
  END b[75]
  PIN b[76]
    DIRECTION OUTPUT ;
    USE SIGNAL ;
    PORT
      LAYER M3 ;
        RECT  20.412 0 20.43 0.037 ;
    END
  END b[76]
  PIN b[77]
    DIRECTION OUTPUT ;
    USE SIGNAL ;
    PORT
      LAYER M3 ;
        RECT  20.484 0 20.502 0.037 ;
    END
  END b[77]
  PIN b[78]
    DIRECTION OUTPUT ;
    USE SIGNAL ;
    PORT
      LAYER M3 ;
        RECT  20.556 0 20.574 0.037 ;
    END
  END b[78]
  PIN b[79]
    DIRECTION OUTPUT ;
    USE SIGNAL ;
    PORT
      LAYER M3 ;
        RECT  20.628 0 20.646 0.037 ;
    END
  END b[79]
  PIN b[7]
    DIRECTION OUTPUT ;
    USE SIGNAL ;
    PORT
      LAYER M3 ;
        RECT  17.748 0 17.766 0.037 ;
    END
  END b[7]
  PIN b[80]
    DIRECTION OUTPUT ;
    USE SIGNAL ;
    PORT
      LAYER M3 ;
        RECT  20.7 0 20.718 0.037 ;
    END
  END b[80]
  PIN b[81]
    DIRECTION OUTPUT ;
    USE SIGNAL ;
    PORT
      LAYER M3 ;
        RECT  20.772 0 20.79 0.037 ;
    END
  END b[81]
  PIN b[82]
    DIRECTION OUTPUT ;
    USE SIGNAL ;
    PORT
      LAYER M3 ;
        RECT  20.844 0 20.862 0.037 ;
    END
  END b[82]
  PIN b[83]
    DIRECTION OUTPUT ;
    USE SIGNAL ;
    PORT
      LAYER M3 ;
        RECT  20.916 0 20.934 0.037 ;
    END
  END b[83]
  PIN b[84]
    DIRECTION OUTPUT ;
    USE SIGNAL ;
    PORT
      LAYER M3 ;
        RECT  20.988 0 21.006 0.037 ;
    END
  END b[84]
  PIN b[85]
    DIRECTION OUTPUT ;
    USE SIGNAL ;
    PORT
      LAYER M3 ;
        RECT  21.06 0 21.078 0.037 ;
    END
  END b[85]
  PIN b[86]
    DIRECTION OUTPUT ;
    USE SIGNAL ;
    PORT
      LAYER M3 ;
        RECT  21.132 0 21.15 0.037 ;
    END
  END b[86]
  PIN b[87]
    DIRECTION OUTPUT ;
    USE SIGNAL ;
    PORT
      LAYER M3 ;
        RECT  21.204 0 21.222 0.037 ;
    END
  END b[87]
  PIN b[88]
    DIRECTION OUTPUT ;
    USE SIGNAL ;
    PORT
      LAYER M3 ;
        RECT  21.276 0 21.294 0.037 ;
    END
  END b[88]
  PIN b[89]
    DIRECTION OUTPUT ;
    USE SIGNAL ;
    PORT
      LAYER M3 ;
        RECT  21.348 0 21.366 0.037 ;
    END
  END b[89]
  PIN b[8]
    DIRECTION OUTPUT ;
    USE SIGNAL ;
    PORT
      LAYER M3 ;
        RECT  17.82 0 17.838 0.037 ;
    END
  END b[8]
  PIN b[90]
    DIRECTION OUTPUT ;
    USE SIGNAL ;
    PORT
      LAYER M3 ;
        RECT  21.42 0 21.438 0.037 ;
    END
  END b[90]
  PIN b[91]
    DIRECTION OUTPUT ;
    USE SIGNAL ;
    PORT
      LAYER M3 ;
        RECT  21.492 0 21.51 0.037 ;
    END
  END b[91]
  PIN b[92]
    DIRECTION OUTPUT ;
    USE SIGNAL ;
    PORT
      LAYER M3 ;
        RECT  21.564 0 21.582 0.037 ;
    END
  END b[92]
  PIN b[93]
    DIRECTION OUTPUT ;
    USE SIGNAL ;
    PORT
      LAYER M3 ;
        RECT  21.636 0 21.654 0.037 ;
    END
  END b[93]
  PIN b[94]
    DIRECTION OUTPUT ;
    USE SIGNAL ;
    PORT
      LAYER M3 ;
        RECT  21.708 0 21.726 0.037 ;
    END
  END b[94]
  PIN b[95]
    DIRECTION OUTPUT ;
    USE SIGNAL ;
    PORT
      LAYER M3 ;
        RECT  21.78 0 21.798 0.037 ;
    END
  END b[95]
  PIN b[96]
    DIRECTION OUTPUT ;
    USE SIGNAL ;
    PORT
      LAYER M3 ;
        RECT  7.452 0 7.47 0.037 ;
    END
  END b[96]
  PIN b[97]
    DIRECTION OUTPUT ;
    USE SIGNAL ;
    PORT
      LAYER M3 ;
        RECT  7.524 0 7.542 0.037 ;
    END
  END b[97]
  PIN b[98]
    DIRECTION OUTPUT ;
    USE SIGNAL ;
    PORT
      LAYER M3 ;
        RECT  7.596 0 7.614 0.037 ;
    END
  END b[98]
  PIN b[99]
    DIRECTION OUTPUT ;
    USE SIGNAL ;
    PORT
      LAYER M3 ;
        RECT  7.668 0 7.686 0.037 ;
    END
  END b[99]
  PIN b[9]
    DIRECTION OUTPUT ;
    USE SIGNAL ;
    PORT
      LAYER M3 ;
        RECT  17.892 0 17.91 0.037 ;
    END
  END b[9]
  PIN ck
    DIRECTION INPUT ;
    USE SIGNAL ;
    PORT
      LAYER M4 ;
        RECT  32.316 39.12 32.4 39.144 ;
    END
  END ck
  PIN ckf
    DIRECTION INPUT ;
    USE SIGNAL ;
    PORT
      LAYER M3 ;
        RECT  9.396 43.163 9.414 43.2 ;
    END
  END ckf
  PIN ea
    DIRECTION INPUT ;
    USE SIGNAL ;
    PORT
      LAYER M3 ;
        RECT  9.468 43.163 9.486 43.2 ;
    END
  END ea
  PIN fault
    DIRECTION OUTPUT ;
    USE SIGNAL ;
    PORT
      LAYER M4 ;
        RECT  32.316 39.216 32.4 39.24 ;
    END
  END fault
  PIN k0
    DIRECTION INPUT ;
    USE SIGNAL ;
    PORT
      LAYER M4 ;
        RECT  32.316 39.312 32.4 39.336 ;
    END
  END k0
  PIN k1
    DIRECTION INPUT ;
    USE SIGNAL ;
    PORT
      LAYER M4 ;
        RECT  32.316 39.408 32.4 39.432 ;
    END
  END k1
  PIN k2
    DIRECTION INPUT ;
    USE SIGNAL ;
    PORT
      LAYER M4 ;
        RECT  32.316 39.504 32.4 39.528 ;
    END
  END k2
  PIN rs
    DIRECTION INPUT ;
    USE SIGNAL ;
    PORT
      LAYER M4 ;
        RECT  32.316 39.6 32.4 39.624 ;
    END
  END rs
  PIN VDD
    DIRECTION INOUT ;
    USE POWER ;
    PORT
      LAYER M5 ;
        RECT  29.592 2.151 29.712 41.049 ;
        RECT  26.892 2.151 27.012 41.049 ;
        RECT  24.192 2.151 24.312 41.049 ;
        RECT  21.492 2.151 21.612 41.049 ;
        RECT  18.792 2.151 18.912 41.049 ;
        RECT  16.092 2.151 16.212 41.049 ;
        RECT  13.392 2.151 13.512 41.049 ;
        RECT  10.692 2.151 10.812 41.049 ;
        RECT  7.992 2.151 8.112 41.049 ;
        RECT  5.292 2.151 5.412 41.049 ;
        RECT  2.592 2.151 2.712 41.049 ;
    END
  END VDD
  PIN VSS
    DIRECTION INOUT ;
    USE GROUND ;
    PORT
      LAYER M5 ;
        RECT  29.4 2.137 29.52 41.063 ;
        RECT  26.7 2.137 26.82 41.063 ;
        RECT  24 2.137 24.12 41.063 ;
        RECT  21.3 2.137 21.42 41.063 ;
        RECT  18.6 2.137 18.72 41.063 ;
        RECT  15.9 2.137 16.02 41.063 ;
        RECT  13.2 2.137 13.32 41.063 ;
        RECT  10.5 2.137 10.62 41.063 ;
        RECT  7.8 2.137 7.92 41.063 ;
        RECT  5.1 2.137 5.22 41.063 ;
        RECT  2.4 2.137 2.52 41.063 ;
    END
  END VSS
  # OT_OBS_CLOSED layer=M5 d_um=1.536 added=110
  OBS
    LAYER RVTN ;
     RECT  2.16 2.16 30.24 2.295 ;
     RECT  2.16 2.565 30.24 2.835 ;
     RECT  2.16 3.105 30.24 3.375 ;
     RECT  2.16 3.645 30.24 3.915 ;
     RECT  2.16 4.185 30.24 4.455 ;
     RECT  2.16 4.725 30.24 4.995 ;
     RECT  2.16 5.265 30.24 5.535 ;
     RECT  2.16 5.805 30.24 6.075 ;
     RECT  2.16 6.345 30.24 6.615 ;
     RECT  2.16 6.885 30.24 7.155 ;
     RECT  2.16 7.425 30.24 7.695 ;
     RECT  2.16 7.965 30.24 8.235 ;
     RECT  2.16 8.505 30.24 8.775 ;
     RECT  2.16 9.045 30.24 9.315 ;
     RECT  2.16 9.585 30.24 9.855 ;
     RECT  2.16 10.125 30.24 10.395 ;
     RECT  2.16 10.665 30.24 10.935 ;
     RECT  2.16 11.205 30.24 11.475 ;
     RECT  2.16 11.745 30.24 12.015 ;
     RECT  2.16 12.285 30.24 12.555 ;
     RECT  2.16 12.825 30.24 13.095 ;
     RECT  2.16 13.365 30.24 13.635 ;
     RECT  2.16 13.905 30.24 14.175 ;
     RECT  2.16 14.445 30.24 14.715 ;
     RECT  2.16 14.985 30.24 15.255 ;
     RECT  2.16 15.525 30.24 15.795 ;
     RECT  2.16 16.065 30.24 16.335 ;
     RECT  2.16 16.605 30.24 16.875 ;
     RECT  2.16 17.145 30.24 17.415 ;
     RECT  2.16 17.685 30.24 17.955 ;
     RECT  2.16 18.225 30.24 18.495 ;
     RECT  2.16 18.765 30.24 19.035 ;
     RECT  2.16 19.305 30.24 19.575 ;
     RECT  2.16 19.845 30.24 20.115 ;
     RECT  2.16 20.385 30.24 20.655 ;
     RECT  2.16 20.925 30.24 21.195 ;
     RECT  2.16 21.465 30.24 21.735 ;
     RECT  2.16 22.005 30.24 22.275 ;
     RECT  2.16 22.545 30.24 22.815 ;
     RECT  2.16 23.085 30.24 23.355 ;
     RECT  2.16 23.625 30.24 23.895 ;
     RECT  2.16 24.165 30.24 24.435 ;
     RECT  2.16 24.705 30.24 24.975 ;
     RECT  2.16 25.245 30.24 25.515 ;
     RECT  2.16 25.785 30.24 26.055 ;
     RECT  2.16 26.325 30.24 26.595 ;
     RECT  2.16 26.865 30.24 27.135 ;
     RECT  2.16 27.405 30.24 27.675 ;
     RECT  2.16 27.945 30.24 28.215 ;
     RECT  2.16 28.485 30.24 28.755 ;
     RECT  2.16 29.025 30.24 29.295 ;
     RECT  2.16 29.565 30.24 29.835 ;
     RECT  2.16 30.105 30.24 30.375 ;
     RECT  2.16 30.645 30.24 30.915 ;
     RECT  2.16 31.185 30.24 31.455 ;
     RECT  2.16 31.725 30.24 31.995 ;
     RECT  2.16 32.265 30.24 32.535 ;
     RECT  2.16 32.805 30.24 33.075 ;
     RECT  2.16 33.345 30.24 33.615 ;
     RECT  2.16 33.885 30.24 34.155 ;
     RECT  2.16 34.425 30.24 34.695 ;
     RECT  2.16 34.965 30.24 35.235 ;
     RECT  2.16 35.505 30.24 35.775 ;
     RECT  2.16 36.045 30.24 36.315 ;
     RECT  2.16 36.585 30.24 36.855 ;
     RECT  2.16 37.125 30.24 37.395 ;
     RECT  2.16 37.665 30.24 37.935 ;
     RECT  2.16 38.205 30.24 38.475 ;
     RECT  2.16 38.745 30.24 39.015 ;
     RECT  2.16 39.285 30.24 39.555 ;
     RECT  2.16 39.825 30.24 40.095 ;
     RECT  2.16 40.365 30.24 40.635 ;
     RECT  2.16 40.905 30.24 41.04 ;
    LAYER RVTP ;
     RECT  2.16 2.295 30.24 2.565 ;
     RECT  2.16 2.835 30.24 3.105 ;
     RECT  2.16 3.375 30.24 3.645 ;
     RECT  2.16 3.915 30.24 4.185 ;
     RECT  2.16 4.455 30.24 4.725 ;
     RECT  2.16 4.995 30.24 5.265 ;
     RECT  2.16 5.535 30.24 5.805 ;
     RECT  2.16 6.075 30.24 6.345 ;
     RECT  2.16 6.615 30.24 6.885 ;
     RECT  2.16 7.155 30.24 7.425 ;
     RECT  2.16 7.695 30.24 7.965 ;
     RECT  2.16 8.235 30.24 8.505 ;
     RECT  2.16 8.775 30.24 9.045 ;
     RECT  2.16 9.315 30.24 9.585 ;
     RECT  2.16 9.855 30.24 10.125 ;
     RECT  2.16 10.395 30.24 10.665 ;
     RECT  2.16 10.935 30.24 11.205 ;
     RECT  2.16 11.475 30.24 11.745 ;
     RECT  2.16 12.015 30.24 12.285 ;
     RECT  2.16 12.555 30.24 12.825 ;
     RECT  2.16 13.095 30.24 13.365 ;
     RECT  2.16 13.635 30.24 13.905 ;
     RECT  2.16 14.175 30.24 14.445 ;
     RECT  2.16 14.715 30.24 14.985 ;
     RECT  2.16 15.255 30.24 15.525 ;
     RECT  2.16 15.795 30.24 16.065 ;
     RECT  2.16 16.335 30.24 16.605 ;
     RECT  2.16 16.875 30.24 17.145 ;
     RECT  2.16 17.415 30.24 17.685 ;
     RECT  2.16 17.955 30.24 18.225 ;
     RECT  2.16 18.495 30.24 18.765 ;
     RECT  2.16 19.035 30.24 19.305 ;
     RECT  2.16 19.575 30.24 19.845 ;
     RECT  2.16 20.115 30.24 20.385 ;
     RECT  2.16 20.655 30.24 20.925 ;
     RECT  2.16 21.195 30.24 21.465 ;
     RECT  2.16 21.735 30.24 22.005 ;
     RECT  2.16 22.275 30.24 22.545 ;
     RECT  2.16 22.815 30.24 23.085 ;
     RECT  2.16 23.355 30.24 23.625 ;
     RECT  2.16 23.895 30.24 24.165 ;
     RECT  2.16 24.435 30.24 24.705 ;
     RECT  2.16 24.975 30.24 25.245 ;
     RECT  2.16 25.515 30.24 25.785 ;
     RECT  2.16 26.055 30.24 26.325 ;
     RECT  2.16 26.595 30.24 26.865 ;
     RECT  2.16 27.135 30.24 27.405 ;
     RECT  2.16 27.675 30.24 27.945 ;
     RECT  2.16 28.215 30.24 28.485 ;
     RECT  2.16 28.755 30.24 29.025 ;
     RECT  2.16 29.295 30.24 29.565 ;
     RECT  2.16 29.835 30.24 30.105 ;
     RECT  2.16 30.375 30.24 30.645 ;
     RECT  2.16 30.915 30.24 31.185 ;
     RECT  2.16 31.455 30.24 31.725 ;
     RECT  2.16 31.995 30.24 32.265 ;
     RECT  2.16 32.535 30.24 32.805 ;
     RECT  2.16 33.075 30.24 33.345 ;
     RECT  2.16 33.615 30.24 33.885 ;
     RECT  2.16 34.155 30.24 34.425 ;
     RECT  2.16 34.695 30.24 34.965 ;
     RECT  2.16 35.235 30.24 35.505 ;
     RECT  2.16 35.775 30.24 36.045 ;
     RECT  2.16 36.315 30.24 36.585 ;
     RECT  2.16 36.855 30.24 37.125 ;
     RECT  2.16 37.395 30.24 37.665 ;
     RECT  2.16 37.935 30.24 38.205 ;
     RECT  2.16 38.475 30.24 38.745 ;
     RECT  2.16 39.015 30.24 39.285 ;
     RECT  2.16 39.555 30.24 39.825 ;
     RECT  2.16 40.095 30.24 40.365 ;
     RECT  2.16 40.635 30.24 40.905 ;
    LAYER M1 ;
     RECT  2.16 2.151 30.24 41.049 ;
    LAYER M2 ;
     RECT  7.483 0.036 7.591 0.054 ;
     RECT  2.16 2.151 7.663 41.049 ;
     RECT  7.591 0.036 8.095 0.198 ;
     RECT  7.663 1.728 8.519 41.049 ;
     RECT  8.095 0.036 8.555 0.279 ;
     RECT  8.555 0.036 9.563 0.162 ;
     RECT  8.519 2.034 9.643 41.049 ;
     RECT  9.563 0.036 9.671 0.09 ;
     RECT  9.671 0.036 11.183 0.054 ;
     RECT  9.643 1.962 11.255 41.049 ;
     RECT  11.255 2.151 14.827 41.049 ;
     RECT  14.827 2.106 17.131 41.049 ;
     RECT  17.131 2.07 17.519 41.049 ;
     RECT  17.519 2.106 17.591 41.049 ;
     RECT  17.671 1.224 17.707 1.242 ;
     RECT  17.707 1.152 17.771 1.242 ;
     RECT  17.771 1.152 18.167 1.17 ;
     RECT  17.095 0.036 18.283 0.054 ;
     RECT  18.283 0.036 18.391 0.126 ;
     RECT  18.391 0.036 18.427 0.198 ;
     RECT  17.591 2.151 18.571 41.049 ;
     RECT  18.427 0.036 18.671 0.279 ;
     RECT  18.571 1.728 18.707 41.049 ;
     RECT  19.003 1.224 19.075 1.242 ;
     RECT  18.671 0.036 19.471 0.09 ;
     RECT  19.075 1.152 19.759 1.242 ;
     RECT  18.707 2.106 19.759 41.049 ;
     RECT  19.759 1.152 20.183 41.049 ;
     RECT  20.183 1.152 20.399 1.17 ;
     RECT  19.471 0.036 20.659 0.126 ;
     RECT  20.659 0.036 20.867 0.198 ;
     RECT  20.183 2.034 21.055 41.049 ;
     RECT  21.055 1.998 21.343 41.049 ;
     RECT  20.867 0.036 21.659 0.126 ;
     RECT  21.659 0.036 22.019 0.09 ;
     RECT  22.019 0.036 22.127 0.054 ;
     RECT  21.343 1.926 23.935 41.049 ;
     RECT  23.935 1.926 24.079 41.634 ;
     RECT  24.079 1.926 24.251 41.706 ;
     RECT  24.295 43.074 24.367 43.092 ;
     RECT  24.367 43.074 24.395 43.164 ;
     RECT  24.251 2.151 24.439 41.706 ;
     RECT  24.395 43.146 24.503 43.164 ;
     RECT  24.439 2.151 25.403 41.742 ;
     RECT  25.403 2.151 25.511 41.706 ;
     RECT  25.511 2.151 27.355 41.049 ;
     RECT  27.355 2.106 27.707 41.049 ;
     RECT  27.707 2.151 30.24 41.049 ;
     RECT  30.24 39.492 30.803 39.51 ;
     RECT  30.24 38.142 31.379 38.16 ;
     RECT  30.24 35.586 32.387 35.604 ;
     RECT  32.287 39.294 32.387 39.312 ;
    LAYER M3 ;
     RECT  17.262 0.012 17.316 0.031 ;
     RECT  17.334 0.012 17.388 0.031 ;
     RECT  17.406 0.012 17.46 0.031 ;
     RECT  17.478 0.012 17.532 0.031 ;
     RECT  17.55 0.012 17.604 0.031 ;
     RECT  17.622 0.012 17.676 0.031 ;
     RECT  17.694 0.012 17.748 0.031 ;
     RECT  17.766 0.012 17.82 0.031 ;
     RECT  17.838 0.012 17.892 0.031 ;
     RECT  17.91 0.012 17.964 0.031 ;
     RECT  17.982 0.012 18.036 0.031 ;
     RECT  18.054 0.012 18.108 0.031 ;
     RECT  18.126 0.012 18.18 0.031 ;
     RECT  18.198 0.012 18.252 0.031 ;
     RECT  18.27 0.012 18.324 0.031 ;
     RECT  18.342 0.012 18.396 0.031 ;
     RECT  18.414 0.012 18.468 0.031 ;
     RECT  18.486 0.012 18.54 0.031 ;
     RECT  18.558 0.012 18.612 0.031 ;
     RECT  18.63 0.012 18.684 0.031 ;
     RECT  18.702 0.012 18.756 0.031 ;
     RECT  18.774 0.012 18.828 0.031 ;
     RECT  18.846 0.012 18.9 0.031 ;
     RECT  18.918 0.012 18.972 0.031 ;
     RECT  18.99 0.012 19.044 0.031 ;
     RECT  19.062 0.012 19.116 0.031 ;
     RECT  19.134 0.012 19.188 0.031 ;
     RECT  19.206 0.012 19.26 0.031 ;
     RECT  19.278 0.012 19.332 0.031 ;
     RECT  19.35 0.012 19.404 0.031 ;
     RECT  19.422 0.012 19.476 0.031 ;
     RECT  19.494 0.012 19.548 0.031 ;
     RECT  19.566 0.012 19.62 0.031 ;
     RECT  19.638 0.012 19.692 0.031 ;
     RECT  19.71 0.012 19.764 0.031 ;
     RECT  19.782 0.012 19.836 0.031 ;
     RECT  19.854 0.012 19.908 0.031 ;
     RECT  19.926 0.012 19.98 0.031 ;
     RECT  19.998 0.012 20.052 0.031 ;
     RECT  20.07 0.012 20.124 0.031 ;
     RECT  20.142 0.012 20.196 0.031 ;
     RECT  20.214 0.012 20.268 0.031 ;
     RECT  20.286 0.012 20.34 0.031 ;
     RECT  20.358 0.012 20.412 0.031 ;
     RECT  20.43 0.012 20.484 0.031 ;
     RECT  20.502 0.012 20.556 0.031 ;
     RECT  20.574 0.012 20.628 0.031 ;
     RECT  20.646 0.012 20.7 0.031 ;
     RECT  20.718 0.012 20.772 0.031 ;
     RECT  20.79 0.012 20.844 0.031 ;
     RECT  20.862 0.012 20.916 0.031 ;
     RECT  20.934 0.012 20.988 0.031 ;
     RECT  21.006 0.012 21.06 0.031 ;
     RECT  21.078 0.012 21.132 0.031 ;
     RECT  21.15 0.012 21.204 0.031 ;
     RECT  21.222 0.012 21.276 0.031 ;
     RECT  21.294 0.012 21.348 0.031 ;
     RECT  21.366 0.012 21.42 0.031 ;
     RECT  21.438 0.012 21.492 0.031 ;
     RECT  21.51 0.012 21.564 0.031 ;
     RECT  21.582 0.012 21.636 0.031 ;
     RECT  21.654 0.012 21.708 0.031 ;
     RECT  21.726 0.012 21.78 0.031 ;
     RECT  26.46 0.091 26.478 0.139 ;
     RECT  26.46 0.139 26.586 0.523 ;
     RECT  26.46 0.523 27.054 0.571 ;
     RECT  28.296 0.091 28.746 0.571 ;
     RECT  26.172 0.571 28.746 1.099 ;
     RECT  11.16 0.031 11.178 1.723 ;
     RECT  26.028 1.099 28.746 1.723 ;
     RECT  26.028 1.723 29.214 1.771 ;
     RECT  10.764 1.723 11.358 1.867 ;
     RECT  23.112 1.993 23.13 2.029 ;
     RECT  7.47 0.012 7.524 0.037 ;
     RECT  7.542 0.012 7.596 0.037 ;
     RECT  7.614 0.012 7.668 0.037 ;
     RECT  7.686 0.012 7.74 0.037 ;
     RECT  7.758 0.012 7.812 0.037 ;
     RECT  7.83 0.012 7.884 0.037 ;
     RECT  7.902 0.012 7.956 0.037 ;
     RECT  7.974 0.012 8.028 0.037 ;
     RECT  8.046 0.012 8.1 0.037 ;
     RECT  8.118 0.012 8.172 0.037 ;
     RECT  8.19 0.012 8.244 0.037 ;
     RECT  8.262 0.012 8.316 0.037 ;
     RECT  8.334 0.012 8.388 0.037 ;
     RECT  8.406 0.012 8.46 0.037 ;
     RECT  8.478 0.012 8.532 0.037 ;
     RECT  8.55 0.012 8.604 0.037 ;
     RECT  8.622 0.012 8.676 0.037 ;
     RECT  8.694 0.012 8.748 0.037 ;
     RECT  8.766 0.012 8.82 0.037 ;
     RECT  8.838 0.012 8.892 0.037 ;
     RECT  8.91 0.012 8.964 0.037 ;
     RECT  8.982 0.012 9.036 0.037 ;
     RECT  9.054 0.012 9.108 0.037 ;
     RECT  9.126 0.012 9.18 0.037 ;
     RECT  9.198 0.012 9.252 0.037 ;
     RECT  9.27 0.012 9.324 0.037 ;
     RECT  9.342 0.012 9.396 0.037 ;
     RECT  9.414 0.012 9.468 0.037 ;
     RECT  9.486 0.012 9.54 0.037 ;
     RECT  9.558 0.012 9.612 0.037 ;
     RECT  9.63 0.012 9.684 0.037 ;
     RECT  7.452 0.037 9.702 2.065 ;
     RECT  7.452 2.065 9.846 2.101 ;
     RECT  10.764 1.867 11.394 2.101 ;
     RECT  23.112 2.029 23.454 2.101 ;
     RECT  24.228 1.921 24.246 2.101 ;
     RECT  12.564 1.819 12.582 2.143 ;
     RECT  17.1 0.031 17.244 0.037 ;
     RECT  17.262 0.031 17.316 0.037 ;
     RECT  17.334 0.031 17.388 0.037 ;
     RECT  17.406 0.031 17.46 0.037 ;
     RECT  17.478 0.031 17.532 0.037 ;
     RECT  17.55 0.031 17.604 0.037 ;
     RECT  17.622 0.031 17.676 0.037 ;
     RECT  17.694 0.031 17.748 0.037 ;
     RECT  17.766 0.031 17.82 0.037 ;
     RECT  17.838 0.031 17.892 0.037 ;
     RECT  17.91 0.031 17.964 0.037 ;
     RECT  17.982 0.031 18.036 0.037 ;
     RECT  18.054 0.031 18.108 0.037 ;
     RECT  18.126 0.031 18.18 0.037 ;
     RECT  18.198 0.031 18.252 0.037 ;
     RECT  18.27 0.031 18.324 0.037 ;
     RECT  18.342 0.031 18.396 0.037 ;
     RECT  18.414 0.031 18.468 0.037 ;
     RECT  18.486 0.031 18.54 0.037 ;
     RECT  18.558 0.031 18.612 0.037 ;
     RECT  18.63 0.031 18.684 0.037 ;
     RECT  18.702 0.031 18.756 0.037 ;
     RECT  18.774 0.031 18.828 0.037 ;
     RECT  18.846 0.031 18.9 0.037 ;
     RECT  18.918 0.031 18.972 0.037 ;
     RECT  18.99 0.031 19.044 0.037 ;
     RECT  19.062 0.031 19.116 0.037 ;
     RECT  19.134 0.031 19.188 0.037 ;
     RECT  19.206 0.031 19.26 0.037 ;
     RECT  19.278 0.031 19.332 0.037 ;
     RECT  19.35 0.031 19.404 0.037 ;
     RECT  19.422 0.031 19.476 0.037 ;
     RECT  19.494 0.031 19.548 0.037 ;
     RECT  19.566 0.031 19.62 0.037 ;
     RECT  19.638 0.031 19.692 0.037 ;
     RECT  19.71 0.031 19.764 0.037 ;
     RECT  19.782 0.031 19.836 0.037 ;
     RECT  19.854 0.031 19.908 0.037 ;
     RECT  19.926 0.031 19.98 0.037 ;
     RECT  19.998 0.031 20.052 0.037 ;
     RECT  20.07 0.031 20.124 0.037 ;
     RECT  20.142 0.031 20.196 0.037 ;
     RECT  20.214 0.031 20.268 0.037 ;
     RECT  20.286 0.031 20.34 0.037 ;
     RECT  20.358 0.031 20.412 0.037 ;
     RECT  20.43 0.031 20.484 0.037 ;
     RECT  20.502 0.031 20.556 0.037 ;
     RECT  20.574 0.031 20.628 0.037 ;
     RECT  20.646 0.031 20.7 0.037 ;
     RECT  20.718 0.031 20.772 0.037 ;
     RECT  20.79 0.031 20.844 0.037 ;
     RECT  20.862 0.031 20.916 0.037 ;
     RECT  20.934 0.031 20.988 0.037 ;
     RECT  21.006 0.031 21.06 0.037 ;
     RECT  21.078 0.031 21.132 0.037 ;
     RECT  21.15 0.031 21.204 0.037 ;
     RECT  21.222 0.031 21.276 0.037 ;
     RECT  21.294 0.031 21.348 0.037 ;
     RECT  21.366 0.031 21.42 0.037 ;
     RECT  21.438 0.031 21.492 0.037 ;
     RECT  21.51 0.031 21.564 0.037 ;
     RECT  21.582 0.031 21.636 0.037 ;
     RECT  21.654 0.031 21.708 0.037 ;
     RECT  21.726 0.031 21.78 0.037 ;
     RECT  21.798 0.031 22.122 0.037 ;
     RECT  17.1 0.037 22.122 2.155 ;
     RECT  15.915 2.143 16.005 2.191 ;
     RECT  17.028 2.155 22.122 2.191 ;
     RECT  7.452 2.101 11.394 2.263 ;
     RECT  14.832 2.101 14.85 2.263 ;
     RECT  15.84 2.191 16.005 2.285 ;
     RECT  14.724 2.263 14.85 2.291 ;
     RECT  12.564 2.143 13.305 2.299 ;
     RECT  17.028 2.191 22.374 2.347 ;
     RECT  23.112 2.101 24.246 2.347 ;
     RECT  6.264 2.191 6.282 2.371 ;
     RECT  7.308 2.263 11.394 2.371 ;
     RECT  12.348 2.299 13.305 2.371 ;
     RECT  17.028 2.347 24.246 2.371 ;
     RECT  26.028 1.771 29.862 2.371 ;
     RECT  2.415 2.143 2.505 2.413 ;
     RECT  5.115 2.143 5.205 2.413 ;
     RECT  6.264 2.371 13.305 2.413 ;
     RECT  15.915 2.285 16.005 2.413 ;
     RECT  5.115 2.413 5.397 2.461 ;
     RECT  6.264 2.413 13.497 2.461 ;
     RECT  15.915 2.413 16.197 2.569 ;
     RECT  16.956 2.371 24.534 2.569 ;
     RECT  3.996 2.461 4.014 2.605 ;
     RECT  15.915 2.569 24.534 2.731 ;
     RECT  3.996 2.605 4.338 2.767 ;
     RECT  15.915 2.731 25.002 2.767 ;
     RECT  26.028 2.371 30.042 2.767 ;
     RECT  3.42 2.767 4.338 2.803 ;
     RECT  5.115 2.461 13.497 2.803 ;
     RECT  15.915 2.767 30.042 2.861 ;
     RECT  14.724 2.291 14.742 3.145 ;
     RECT  2.415 2.413 2.697 3.181 ;
     RECT  3.42 2.803 13.497 3.181 ;
     RECT  2.415 3.181 13.497 3.343 ;
     RECT  25.884 2.861 30.042 3.569 ;
     RECT  15.915 2.861 25.002 3.649 ;
     RECT  2.415 3.343 13.59 3.685 ;
     RECT  15.876 3.649 25.074 3.721 ;
     RECT  15.876 3.721 25.11 3.811 ;
     RECT  2.376 3.685 13.59 3.883 ;
     RECT  14.688 3.145 14.742 3.883 ;
     RECT  2.376 3.883 14.742 4.189 ;
     RECT  2.376 4.189 14.85 4.289 ;
     RECT  15.876 3.811 25.218 4.459 ;
     RECT  25.992 3.569 30.042 4.459 ;
     RECT  15.876 4.459 30.042 4.495 ;
     RECT  15.876 4.495 30.114 4.649 ;
     RECT  2.415 4.289 14.85 4.999 ;
     RECT  15.876 4.649 29.754 5.575 ;
     RECT  2.415 4.999 15.138 5.611 ;
     RECT  15.876 5.575 29.79 5.611 ;
     RECT  2.415 5.611 29.79 5.881 ;
     RECT  2.415 5.881 29.898 6.808 ;
     RECT  2.412 6.808 29.898 6.809 ;
     RECT  2.412 6.809 29.697 6.845 ;
     RECT  2.415 6.845 29.697 8.005 ;
     RECT  2.415 8.005 29.862 8.473 ;
     RECT  2.415 8.473 29.898 9.895 ;
     RECT  2.415 9.895 30.114 10.049 ;
     RECT  2.415 10.049 29.898 10.831 ;
     RECT  2.415 10.831 29.97 11.227 ;
     RECT  2.376 11.227 29.97 11.399 ;
     RECT  2.415 11.399 29.97 13.739 ;
     RECT  2.415 13.739 29.898 16.231 ;
     RECT  2.376 16.231 29.898 16.301 ;
     RECT  2.415 16.301 29.898 18.733 ;
     RECT  2.415 18.733 29.97 24.809 ;
     RECT  2.415 24.809 3.294 25.555 ;
     RECT  4.068 24.809 29.97 25.555 ;
     RECT  2.415 25.555 29.97 29.759 ;
     RECT  6.336 29.759 29.97 31.531 ;
     RECT  6.336 31.531 30.006 31.649 ;
     RECT  6.336 31.649 6.642 31.765 ;
     RECT  6.12 31.765 6.642 31.805 ;
     RECT  7.452 31.649 30.006 31.991 ;
     RECT  6.336 31.805 6.642 32.443 ;
     RECT  7.452 31.991 29.97 32.443 ;
     RECT  6.336 32.443 29.97 32.495 ;
     RECT  7.524 32.495 29.97 33.809 ;
     RECT  2.415 29.759 5.397 33.925 ;
     RECT  6.336 32.495 6.642 33.925 ;
     RECT  2.415 33.925 6.642 33.965 ;
     RECT  7.815 33.809 29.97 34.529 ;
     RECT  7.815 34.529 29.934 35.429 ;
     RECT  12.276 35.429 29.79 35.465 ;
     RECT  7.815 35.429 9.522 35.699 ;
     RECT  10.44 35.429 11.394 35.969 ;
     RECT  12.276 35.465 29.697 36.355 ;
     RECT  12.276 36.355 29.79 36.517 ;
     RECT  12.276 36.517 29.934 36.823 ;
     RECT  12.06 36.823 29.934 36.851 ;
     RECT  12.06 36.851 25.506 36.895 ;
     RECT  26.388 36.851 29.934 37.049 ;
     RECT  26.388 37.049 29.79 37.085 ;
     RECT  26.388 37.085 29.697 37.133 ;
     RECT  11.808 36.895 25.506 37.625 ;
     RECT  32.364 35.581 32.382 39.019 ;
     RECT  26.496 37.133 29.697 39.091 ;
     RECT  10.44 35.969 11.07 39.209 ;
     RECT  26.496 39.091 30.186 39.245 ;
     RECT  7.815 35.699 9.054 39.289 ;
     RECT  32.292 39.019 32.382 39.317 ;
     RECT  32.292 39.317 32.31 39.341 ;
     RECT  10.515 39.209 11.07 39.361 ;
     RECT  10.515 39.361 11.25 39.479 ;
     RECT  31.356 38.137 31.374 39.487 ;
     RECT  30.78 39.487 31.374 39.533 ;
     RECT  26.496 39.245 29.697 39.587 ;
     RECT  7.815 39.289 9.126 39.595 ;
     RECT  30.78 39.533 30.798 39.629 ;
     RECT  26.496 39.587 26.997 39.749 ;
     RECT  7.815 39.595 9.342 39.865 ;
     RECT  10.515 39.479 11.07 40.019 ;
     RECT  27.792 39.587 29.697 40.019 ;
     RECT  6.336 33.965 6.642 40.063 ;
     RECT  12.276 37.625 25.506 40.091 ;
     RECT  6.12 40.063 6.642 40.099 ;
     RECT  7.488 39.865 9.342 40.099 ;
     RECT  6.12 40.099 9.342 40.289 ;
     RECT  27.828 40.019 29.697 40.289 ;
     RECT  2.415 33.965 5.397 40.297 ;
     RECT  6.12 40.289 8.097 40.297 ;
     RECT  22.464 40.091 25.506 40.469 ;
     RECT  2.415 40.297 8.097 40.541 ;
     RECT  10.515 40.019 10.89 40.559 ;
     RECT  28.512 40.289 28.53 40.559 ;
     RECT  8.82 40.289 9.342 40.603 ;
     RECT  2.415 40.541 6.138 40.787 ;
     RECT  7.488 40.541 8.097 40.787 ;
     RECT  10.515 40.559 10.797 40.787 ;
     RECT  12.276 40.091 21.597 40.787 ;
     RECT  26.715 39.749 26.997 40.787 ;
     RECT  29.415 40.289 29.697 40.787 ;
     RECT  3.276 40.787 6.138 40.973 ;
     RECT  12.276 40.787 21.405 40.973 ;
     RECT  12.276 40.973 19.674 41.009 ;
     RECT  20.664 40.973 21.405 41.009 ;
     RECT  7.488 40.787 7.905 41.021 ;
     RECT  12.276 41.009 19.35 41.021 ;
     RECT  2.415 40.787 2.505 41.057 ;
     RECT  7.815 41.021 7.905 41.057 ;
     RECT  10.515 40.787 10.605 41.057 ;
     RECT  21.315 41.009 21.405 41.057 ;
     RECT  26.715 40.787 26.805 41.057 ;
     RECT  29.415 40.787 29.505 41.057 ;
     RECT  12.276 41.021 16.326 41.069 ;
     RECT  3.276 40.973 5.454 41.165 ;
     RECT  18.576 41.021 19.026 41.165 ;
     RECT  18.576 41.165 18.99 41.213 ;
     RECT  18.756 41.213 18.99 41.261 ;
     RECT  12.276 41.069 16.29 41.645 ;
     RECT  12.996 41.645 15.498 41.693 ;
     RECT  22.644 40.469 25.506 41.711 ;
     RECT  22.644 41.711 25.398 41.747 ;
     RECT  13.716 41.693 15.462 41.837 ;
     RECT  13.716 41.837 15.138 42.173 ;
     RECT  3.276 41.165 5.274 42.221 ;
     RECT  17.46 41.021 17.478 42.221 ;
     RECT  3.492 42.221 5.274 42.269 ;
     RECT  3.888 42.269 5.274 42.859 ;
     RECT  13.716 42.173 14.958 42.941 ;
     RECT  3.888 42.859 5.562 43.051 ;
     RECT  3.888 43.051 5.67 43.085 ;
     RECT  13.716 42.941 14.886 43.085 ;
     RECT  15.912 42.955 15.93 43.085 ;
     RECT  5.652 43.085 5.67 43.181 ;
     RECT  8.82 40.603 9.486 43.163 ;
     RECT  8.838 43.163 8.892 43.181 ;
     RECT  8.91 43.163 8.964 43.181 ;
     RECT  8.982 43.163 9.036 43.181 ;
     RECT  9.054 43.163 9.108 43.181 ;
     RECT  9.126 43.163 9.18 43.181 ;
     RECT  9.198 43.163 9.252 43.181 ;
     RECT  9.27 43.163 9.324 43.181 ;
     RECT  9.342 43.163 9.396 43.181 ;
     RECT  9.414 43.163 9.468 43.181 ;
     RECT  22.644 41.747 24.894 43.163 ;
     RECT  22.662 43.163 22.716 43.181 ;
     RECT  22.734 43.163 22.788 43.181 ;
     RECT  22.806 43.163 22.86 43.181 ;
     RECT  22.878 43.163 22.932 43.181 ;
     RECT  22.95 43.163 23.004 43.181 ;
     RECT  23.022 43.163 23.076 43.181 ;
     RECT  23.094 43.163 23.148 43.181 ;
     RECT  23.166 43.163 23.22 43.181 ;
     RECT  23.238 43.163 23.292 43.181 ;
     RECT  23.31 43.163 23.364 43.181 ;
     RECT  23.382 43.163 23.436 43.181 ;
     RECT  23.454 43.163 23.508 43.181 ;
     RECT  23.526 43.163 23.58 43.181 ;
     RECT  23.598 43.163 23.652 43.181 ;
     RECT  23.67 43.163 23.724 43.181 ;
     RECT  23.742 43.163 23.796 43.181 ;
     RECT  23.814 43.163 23.868 43.181 ;
     RECT  23.886 43.163 23.94 43.181 ;
     RECT  23.958 43.163 24.012 43.181 ;
     RECT  24.03 43.163 24.084 43.181 ;
     RECT  24.102 43.163 24.156 43.181 ;
     RECT  24.174 43.163 24.228 43.181 ;
     RECT  24.246 43.163 24.3 43.181 ;
     RECT  24.318 43.163 24.372 43.181 ;
     RECT  24.39 43.163 24.444 43.181 ;
     RECT  24.462 43.163 24.516 43.181 ;
     RECT  24.534 43.163 24.588 43.181 ;
     RECT  24.606 43.163 24.66 43.181 ;
     RECT  24.678 43.163 24.732 43.181 ;
     RECT  24.75 43.163 24.804 43.181 ;
     RECT  24.822 43.163 24.876 43.181 ;
    LAYER M4 ;
     RECT  2.401 6.816 2.408 6.84 ;
     RECT  2.365 11.232 2.408 11.256 ;
     RECT  2.365 16.272 2.408 16.296 ;
     RECT  2.408 2.148 2.512 41.052 ;
     RECT  2.512 2.418 2.704 40.782 ;
     RECT  2.704 11.232 2.819 16.296 ;
     RECT  2.704 6.24 2.837 8.136 ;
     RECT  2.704 9.744 2.837 9.768 ;
     RECT  2.837 6.24 2.909 7.992 ;
     RECT  3.157 43.056 3.265 43.08 ;
     RECT  3.265 42.192 3.445 43.08 ;
     RECT  3.445 42.096 3.532 43.08 ;
     RECT  3.532 42.24 3.565 43.08 ;
     RECT  2.704 22.08 3.593 22.248 ;
     RECT  2.819 11.232 3.629 14.472 ;
     RECT  2.704 28.464 3.673 28.488 ;
     RECT  3.593 22.08 3.805 22.104 ;
     RECT  3.629 11.232 3.997 11.976 ;
     RECT  2.704 24.528 4.093 24.552 ;
     RECT  3.629 13.296 4.133 14.472 ;
     RECT  4.093 24.528 4.133 25.08 ;
     RECT  2.704 18.24 4.165 18.264 ;
     RECT  2.704 19.776 4.165 19.8 ;
     RECT  3.997 11.232 4.201 11.304 ;
     RECT  2.819 16.272 4.381 16.296 ;
     RECT  4.417 41.088 4.453 41.112 ;
     RECT  3.805 21.648 4.561 22.104 ;
     RECT  2.704 3.408 4.693 3.432 ;
     RECT  4.693 2.832 4.741 3.432 ;
     RECT  4.165 18.24 4.777 19.8 ;
     RECT  3.565 42.816 4.837 43.08 ;
     RECT  4.133 13.296 4.892 13.992 ;
     RECT  4.837 42.528 4.979 43.08 ;
     RECT  4.777 18.144 4.981 19.8 ;
     RECT  4.561 21.12 4.981 22.104 ;
     RECT  4.741 2.832 5.108 3.912 ;
     RECT  2.909 6.24 5.108 6.264 ;
     RECT  2.909 7.968 5.108 7.992 ;
     RECT  4.165 9.36 5.108 9.384 ;
     RECT  4.201 10.896 5.108 11.304 ;
     RECT  4.892 12.912 5.108 13.992 ;
     RECT  4.381 16.272 5.108 16.584 ;
     RECT  4.981 18.144 5.108 22.104 ;
     RECT  4.268 23.136 5.108 23.16 ;
     RECT  4.133 25.056 5.108 25.08 ;
     RECT  4.309 26.736 5.108 26.76 ;
     RECT  4.7 28.8 5.108 28.824 ;
     RECT  4.357 29.904 5.108 29.928 ;
     RECT  4.453 40.992 5.108 41.112 ;
     RECT  5.108 2.148 5.212 41.112 ;
     RECT  5.212 2.418 5.381 41.112 ;
     RECT  5.381 2.418 5.404 41.16 ;
     RECT  5.404 40.416 5.465 41.16 ;
     RECT  5.404 17.616 5.537 21.432 ;
     RECT  4.979 42.768 5.555 43.08 ;
     RECT  5.404 12.528 5.573 13.32 ;
     RECT  5.404 24.432 5.603 25.08 ;
     RECT  5.555 42.864 5.603 43.08 ;
     RECT  5.537 21.12 5.609 21.432 ;
     RECT  5.603 42.96 5.612 43.08 ;
     RECT  5.573 12.528 5.651 13.032 ;
     RECT  5.612 42.96 5.651 43.176 ;
     RECT  5.651 43.056 5.681 43.176 ;
     RECT  5.404 26.928 5.699 27.768 ;
     RECT  5.681 43.152 5.699 43.176 ;
     RECT  5.404 7.968 5.717 11.208 ;
     RECT  5.404 6.24 5.825 6.696 ;
     RECT  5.717 9.936 5.861 11.208 ;
     RECT  5.404 3.888 5.897 3.912 ;
     RECT  5.825 6.24 5.969 6.264 ;
     RECT  5.861 11.184 5.987 11.208 ;
     RECT  5.404 33.936 6.005 33.96 ;
     RECT  5.609 21.408 6.113 21.432 ;
     RECT  5.404 31.776 6.149 32.472 ;
     RECT  5.537 17.616 6.275 19.56 ;
     RECT  5.699 27.744 6.437 27.768 ;
     RECT  5.404 14.688 6.509 15.192 ;
     RECT  5.717 7.968 6.541 8.904 ;
     RECT  6.275 19.248 6.541 19.56 ;
     RECT  5.603 24.432 6.613 24.936 ;
     RECT  6.541 19.248 6.689 19.944 ;
     RECT  6.541 7.344 6.757 8.904 ;
     RECT  5.861 9.936 6.757 9.96 ;
     RECT  6.253 2.208 6.829 2.232 ;
     RECT  5.651 13.008 6.901 13.032 ;
     RECT  6.829 2.208 6.973 3.336 ;
     RECT  6.509 15.168 7.009 15.192 ;
     RECT  6.901 12.72 7.045 13.032 ;
     RECT  6.973 2.208 7.153 4.248 ;
     RECT  6.613 24.432 7.549 25.128 ;
     RECT  5.404 29.76 7.585 29.784 ;
     RECT  7.549 24.432 7.621 25.224 ;
     RECT  7.153 2.208 7.669 5.064 ;
     RECT  7.117 27.888 7.693 27.912 ;
     RECT  7.669 2.064 7.808 5.304 ;
     RECT  7.436 6.288 7.808 6.312 ;
     RECT  6.757 7.344 7.808 9.96 ;
     RECT  7.045 11.952 7.808 13.032 ;
     RECT  7.009 15.168 7.808 16.008 ;
     RECT  6.275 17.616 7.808 18.216 ;
     RECT  6.689 19.92 7.808 19.944 ;
     RECT  6.901 22.32 7.808 22.344 ;
     RECT  6.505 23.328 7.808 23.352 ;
     RECT  7.621 24.384 7.808 25.224 ;
     RECT  7.693 27.888 7.808 28.536 ;
     RECT  7.585 29.76 7.808 30.168 ;
     RECT  6.149 32.448 7.808 32.472 ;
     RECT  5.465 40.416 7.808 41.016 ;
     RECT  7.808 2.064 7.912 41.052 ;
     RECT  7.912 2.064 8.104 40.782 ;
     RECT  8.104 14.208 8.165 16.392 ;
     RECT  8.104 17.616 8.165 18.216 ;
     RECT  8.165 16.08 8.201 16.392 ;
     RECT  8.104 6.144 8.237 8.52 ;
     RECT  8.201 16.08 8.237 16.104 ;
     RECT  8.165 17.616 8.489 18.168 ;
     RECT  8.104 30.144 8.531 30.744 ;
     RECT  8.165 14.208 8.561 15.096 ;
     RECT  8.237 6.144 8.579 6.84 ;
     RECT  8.104 2.064 8.597 5.064 ;
     RECT  8.489 17.616 8.597 17.976 ;
     RECT  8.104 27.888 8.705 29.112 ;
     RECT  8.705 28.512 8.769 29.112 ;
     RECT  8.104 26.496 9.097 26.52 ;
     RECT  8.561 14.208 9.101 15 ;
     RECT  8.104 24.384 9.107 25.464 ;
     RECT  8.104 31.728 9.107 31.944 ;
     RECT  9.107 25.44 9.109 25.464 ;
     RECT  9.097 26.496 9.109 27.384 ;
     RECT  8.597 2.544 9.137 5.064 ;
     RECT  9.109 25.44 9.181 27.384 ;
     RECT  8.104 19.2 9.245 21.096 ;
     RECT  9.181 25.44 9.245 26.52 ;
     RECT  9.107 31.728 9.349 31.752 ;
     RECT  8.769 29.088 9.389 29.112 ;
     RECT  9.356 43.104 9.443 43.128 ;
     RECT  8.104 11.232 9.533 11.256 ;
     RECT  8.579 6.816 9.644 6.84 ;
     RECT  8.237 8.16 9.644 8.52 ;
     RECT  9.137 2.784 9.673 5.064 ;
     RECT  9.245 20.88 9.673 21.096 ;
     RECT  9.644 6.816 9.745 8.52 ;
     RECT  9.745 6.816 9.781 9.096 ;
     RECT  9.673 20.88 9.817 21.144 ;
     RECT  8.104 34.416 9.82 34.44 ;
     RECT  9.673 2.784 10.213 5.256 ;
     RECT  9.781 6.432 10.213 9.096 ;
     RECT  9.101 14.496 10.241 15 ;
     RECT  10.249 25.152 10.357 25.176 ;
     RECT  9.245 26.208 10.357 26.52 ;
     RECT  9.349 30.864 10.357 31.752 ;
     RECT  9.817 20.88 10.393 21.528 ;
     RECT  10.213 2.784 10.508 9.096 ;
     RECT  9.5 13.344 10.508 13.368 ;
     RECT  10.241 14.496 10.508 15.432 ;
     RECT  8.597 17.616 10.508 17.64 ;
     RECT  9.245 19.2 10.508 19.416 ;
     RECT  10.393 20.4 10.508 21.528 ;
     RECT  9.109 23.712 10.508 23.736 ;
     RECT  10.357 25.152 10.508 26.52 ;
     RECT  10.357 27.84 10.508 28.2 ;
     RECT  10.357 30.144 10.508 31.752 ;
     RECT  9.82 34.416 10.508 34.488 ;
     RECT  10.508 2.148 10.612 41.052 ;
     RECT  10.357 0.096 10.739 0.12 ;
     RECT  10.612 2.148 10.748 40.782 ;
     RECT  10.748 1.728 10.804 40.782 ;
     RECT  10.804 25.44 10.829 25.992 ;
     RECT  10.804 29.232 10.829 31.752 ;
     RECT  10.829 25.536 10.865 25.992 ;
     RECT  10.804 1.728 10.973 5.832 ;
     RECT  10.804 18.96 11.045 22.488 ;
     RECT  10.804 8.16 11.081 8.52 ;
     RECT  10.973 1.728 11.123 3.336 ;
     RECT  11.123 1.728 11.369 2.904 ;
     RECT  10.804 34.464 11.405 34.488 ;
     RECT  11.369 1.824 11.411 2.904 ;
     RECT  10.804 7.056 11.651 7.08 ;
     RECT  11.081 8.16 11.651 8.184 ;
     RECT  10.804 17.472 11.797 17.64 ;
     RECT  11.045 18.96 11.797 18.984 ;
     RECT  11.411 2.88 11.837 2.904 ;
     RECT  10.804 16.128 11.843 16.152 ;
     RECT  11.797 17.472 11.843 18.984 ;
     RECT  10.829 30.864 11.945 31.752 ;
     RECT  10.973 4.8 11.989 5.832 ;
     RECT  10.804 13.824 12.013 13.848 ;
     RECT  11.989 3.936 12.076 5.832 ;
     RECT  11.989 24.096 12.076 24.12 ;
     RECT  10.865 25.728 12.089 25.992 ;
     RECT  11.045 20.88 12.161 22.488 ;
     RECT  11.945 31.392 12.337 31.752 ;
     RECT  12.161 20.88 12.373 21.528 ;
     RECT  10.829 29.232 12.373 29.256 ;
     RECT  12.013 13.824 12.481 14.136 ;
     RECT  11.797 37.056 12.481 37.08 ;
     RECT  12.481 37.056 12.517 37.224 ;
     RECT  11.411 1.824 12.593 1.848 ;
     RECT  12.373 33.216 12.661 33.24 ;
     RECT  12.409 9.072 12.733 9.096 ;
     RECT  12.085 10.08 12.733 10.104 ;
     RECT  12.332 27.312 12.913 27.336 ;
     RECT  12.265 41.616 12.913 41.64 ;
     RECT  12.373 16.368 12.985 16.392 ;
     RECT  11.843 17.616 12.985 18.984 ;
     RECT  12.913 41.136 12.985 41.64 ;
     RECT  10.804 11.376 13.093 11.4 ;
     RECT  11.905 12.384 13.093 12.408 ;
     RECT  12.481 13.824 13.093 14.232 ;
     RECT  12.337 31.392 13.093 31.8 ;
     RECT  12.661 33.072 13.093 33.24 ;
     RECT  12.949 35.808 13.093 35.832 ;
     RECT  13.093 35.184 13.165 35.832 ;
     RECT  12.076 4.8 13.208 5.832 ;
     RECT  12.733 9.072 13.208 10.104 ;
     RECT  13.093 11.376 13.208 12.408 ;
     RECT  13.093 13.824 13.208 14.424 ;
     RECT  12.985 16.368 13.208 18.984 ;
     RECT  12.373 19.968 13.208 21.528 ;
     RECT  12.625 23.04 13.208 23.064 ;
     RECT  12.089 25.968 13.208 25.992 ;
     RECT  12.913 26.976 13.208 27.336 ;
     RECT  12.373 28.512 13.208 29.256 ;
     RECT  13.093 31.392 13.208 33.24 ;
     RECT  13.165 34.992 13.208 35.832 ;
     RECT  12.517 37.056 13.208 37.656 ;
     RECT  12.553 39.792 13.208 39.816 ;
     RECT  12.985 41.136 13.208 41.688 ;
     RECT  13.208 2.148 13.312 41.688 ;
     RECT  13.312 2.418 13.504 41.688 ;
     RECT  13.504 11.376 13.529 15.336 ;
     RECT  13.504 27.072 13.601 27.096 ;
     RECT  13.529 12.528 13.619 15.336 ;
     RECT  13.504 16.368 13.681 18.792 ;
     RECT  13.661 43.056 13.744 43.08 ;
     RECT  13.504 20.88 13.781 23.064 ;
     RECT  13.744 43.008 13.813 43.08 ;
     RECT  13.619 12.528 13.853 12.552 ;
     RECT  13.681 16.368 13.889 17.112 ;
     RECT  13.504 24.288 13.889 25.944 ;
     RECT  13.619 13.584 13.9 15.336 ;
     RECT  13.504 4.944 13.961 7.176 ;
     RECT  13.813 42.912 14.005 43.08 ;
     RECT  13.681 18.192 14.149 18.792 ;
     RECT  13.504 30.72 14.243 36.12 ;
     RECT  13.504 37.248 14.243 38.376 ;
     RECT  13.529 11.376 14.291 11.4 ;
     RECT  14.243 37.584 14.291 38.376 ;
     RECT  13.9 13.584 14.465 14.424 ;
     RECT  14.243 30.72 14.637 33.624 ;
     RECT  13.889 25.296 14.677 25.944 ;
     RECT  14.637 30.72 14.681 33.144 ;
     RECT  14.243 36.096 14.753 36.12 ;
     RECT  13.504 39.456 14.771 41.688 ;
     RECT  13.961 6.288 14.773 7.176 ;
     RECT  13.504 8.64 14.773 8.664 ;
     RECT  13.781 20.88 14.785 21.528 ;
     RECT  14.773 6.288 14.819 8.664 ;
     RECT  13.889 24.288 14.821 24.312 ;
     RECT  13.889 16.368 14.857 16.968 ;
     RECT  14.149 18.192 14.857 18.264 ;
     RECT  14.785 19.92 14.861 21.528 ;
     RECT  14.819 6.288 14.897 6.312 ;
     RECT  14.243 34.752 14.897 35.064 ;
     RECT  13.504 28.368 14.929 28.392 ;
     RECT  14.465 13.68 14.993 14.424 ;
     RECT  14.861 19.92 15.001 21.192 ;
     RECT  14.857 16.368 15.037 18.264 ;
     RECT  14.771 41.616 15.109 41.688 ;
     RECT  14.005 42.816 15.109 43.08 ;
     RECT  14.677 25.296 15.205 26.808 ;
     RECT  14.929 27.888 15.205 28.392 ;
     RECT  14.993 13.68 15.289 14.856 ;
     RECT  15.037 15.84 15.289 18.264 ;
     RECT  15.205 25.296 15.317 28.392 ;
     RECT  14.821 24.24 15.469 24.312 ;
     RECT  15.317 25.296 15.469 28.488 ;
     RECT  15.289 13.68 15.637 18.264 ;
     RECT  14.897 35.04 15.685 35.064 ;
     RECT  14.681 30.912 15.865 33.144 ;
     RECT  15.829 2.256 15.908 2.28 ;
     RECT  13.961 4.944 15.908 4.968 ;
     RECT  14.819 7.584 15.908 8.568 ;
     RECT  13.504 9.888 15.908 9.912 ;
     RECT  15.637 13.68 15.908 18.744 ;
     RECT  15.001 19.776 15.908 21.192 ;
     RECT  15.469 24.24 15.908 28.488 ;
     RECT  15.865 30.912 15.908 33.624 ;
     RECT  15.685 35.04 15.908 35.448 ;
     RECT  14.291 37.584 15.908 37.608 ;
     RECT  14.771 39.456 15.908 40.536 ;
     RECT  15.109 41.616 15.908 43.08 ;
     RECT  15.908 2.148 15.923 43.08 ;
     RECT  15.923 42.96 15.974 43.08 ;
     RECT  15.923 2.148 16.012 41.832 ;
     RECT  16.012 2.256 16.204 41.832 ;
     RECT  16.204 40.464 16.307 41.832 ;
     RECT  16.204 7.584 16.373 8.568 ;
     RECT  16.204 39.216 16.409 39.48 ;
     RECT  15.974 43.008 16.451 43.032 ;
     RECT  16.204 33.6 16.589 34.056 ;
     RECT  16.204 35.424 16.589 35.688 ;
     RECT  16.204 17.088 16.805 20.136 ;
     RECT  16.204 24.48 16.835 31.992 ;
     RECT  16.204 10.992 16.841 11.976 ;
     RECT  16.805 18.912 16.931 20.136 ;
     RECT  16.307 40.464 16.979 41.64 ;
     RECT  16.204 2.256 17.017 5.976 ;
     RECT  16.835 27.696 17.057 31.992 ;
     RECT  16.979 40.464 17.075 41.064 ;
     RECT  16.204 22.8 17.093 23.496 ;
     RECT  16.409 39.216 17.093 39.24 ;
     RECT  16.805 17.088 17.123 17.88 ;
     RECT  17.017 2.16 17.173 5.976 ;
     RECT  16.373 7.584 17.173 8.52 ;
     RECT  17.173 2.16 17.237 8.52 ;
     RECT  17.237 4.368 17.26 8.52 ;
     RECT  16.931 19.872 17.269 20.136 ;
     RECT  16.204 21.168 17.269 21.192 ;
     RECT  16.589 35.664 17.317 35.688 ;
     RECT  16.204 37.536 17.317 38.184 ;
     RECT  16.204 13.392 17.449 14.904 ;
     RECT  17.237 2.16 17.453 3.048 ;
     RECT  17.123 17.184 17.453 17.88 ;
     RECT  17.093 22.8 17.561 23.4 ;
     RECT  17.057 27.696 17.596 29.352 ;
     RECT  17.449 42.192 17.843 42.216 ;
     RECT  17.057 30.336 17.881 31.992 ;
     RECT  16.835 24.48 17.989 26.664 ;
     RECT  17.317 35.664 17.989 38.184 ;
     RECT  17.413 15.936 17.996 15.96 ;
     RECT  17.989 24.48 18.061 27.192 ;
     RECT  17.596 28.464 18.061 29.352 ;
     RECT  17.881 30.336 18.061 32.28 ;
     RECT  17.26 7.584 18.133 8.52 ;
     RECT  17.269 19.872 18.181 21.192 ;
     RECT  16.589 34.032 18.205 34.056 ;
     RECT  17.989 35.664 18.205 39.048 ;
     RECT  18.205 34.032 18.241 39.048 ;
     RECT  18.241 33.696 18.284 39.048 ;
     RECT  16.841 10.992 18.313 11.016 ;
     RECT  18.284 33.696 18.313 39.336 ;
     RECT  17.453 2.304 18.38 3.048 ;
     RECT  17.26 4.368 18.38 6.504 ;
     RECT  18.313 10.8 18.385 11.016 ;
     RECT  18.313 33.6 18.385 39.336 ;
     RECT  18.385 10.704 18.421 11.016 ;
     RECT  17.996 15.936 18.421 16.2 ;
     RECT  17.453 17.184 18.421 17.208 ;
     RECT  18.385 33.552 18.421 39.336 ;
     RECT  17.075 40.464 18.421 41.016 ;
     RECT  18.133 7.584 18.449 9.096 ;
     RECT  18.421 10.08 18.449 11.016 ;
     RECT  18.061 28.464 18.457 32.28 ;
     RECT  18.421 33.552 18.565 41.016 ;
     RECT  18.457 0.096 18.569 0.12 ;
     RECT  18.38 2.304 18.608 6.504 ;
     RECT  18.449 7.584 18.608 11.016 ;
     RECT  17.449 13.344 18.608 14.904 ;
     RECT  18.421 15.936 18.608 17.208 ;
     RECT  18.181 19.008 18.608 21.192 ;
     RECT  17.561 23.04 18.608 23.4 ;
     RECT  18.061 24.432 18.608 27.192 ;
     RECT  18.457 28.464 18.608 32.52 ;
     RECT  18.565 33.552 18.608 41.208 ;
     RECT  18.608 2.148 18.648 41.208 ;
     RECT  18.648 2.148 18.712 41.256 ;
     RECT  18.421 43.008 18.803 43.032 ;
     RECT  18.712 2.418 18.904 41.256 ;
     RECT  18.904 38.784 19.001 41.256 ;
     RECT  18.904 29.232 19.037 32.28 ;
     RECT  19.001 38.784 19.037 41.16 ;
     RECT  18.904 23.232 19.073 23.352 ;
     RECT  18.904 26.016 19.109 27.72 ;
     RECT  19.037 29.232 19.109 32.232 ;
     RECT  18.904 16.992 19.217 21.576 ;
     RECT  18.904 24.624 19.217 24.648 ;
     RECT  19.109 29.232 19.217 31.944 ;
     RECT  19.073 23.232 19.283 23.256 ;
     RECT  19.037 38.784 19.361 41.016 ;
     RECT  18.904 33.6 19.433 33.624 ;
     RECT  18.904 2.928 19.577 9.096 ;
     RECT  18.904 13.344 19.613 15.432 ;
     RECT  19.217 16.992 19.613 19.128 ;
     RECT  19.217 29.232 19.667 30.792 ;
     RECT  19.667 29.808 19.829 30.792 ;
     RECT  19.217 31.776 19.829 31.944 ;
     RECT  18.904 10.992 19.865 11.016 ;
     RECT  19.577 6.096 19.897 9.096 ;
     RECT  19.613 18.144 19.955 19.128 ;
     RECT  18.904 36.528 19.969 37.608 ;
     RECT  19.829 30.24 20.003 30.792 ;
     RECT  19.361 38.784 20.005 40.968 ;
     RECT  19.217 20.352 20.045 21.576 ;
     RECT  19.969 36.144 20.051 37.608 ;
     RECT  20.005 38.64 20.092 40.968 ;
     RECT  20.092 39.024 20.189 40.968 ;
     RECT  20.045 20.448 20.221 21.576 ;
     RECT  20.051 36.144 20.291 36.696 ;
     RECT  20.189 40.032 20.291 40.296 ;
     RECT  19.613 16.992 20.401 17.016 ;
     RECT  20.401 11.712 20.473 11.736 ;
     RECT  19.955 19.008 20.509 19.128 ;
     RECT  19.613 13.344 20.533 14.856 ;
     RECT  19.577 2.928 20.629 5.112 ;
     RECT  19.897 6.096 20.629 9.96 ;
     RECT  20.629 2.928 20.833 9.96 ;
     RECT  19.829 31.824 20.833 31.944 ;
     RECT  20.401 16.656 21.049 17.016 ;
     RECT  19.109 26.256 21.068 27.72 ;
     RECT  20.473 11.712 21.109 11.976 ;
     RECT  20.533 13.296 21.109 14.856 ;
     RECT  21.109 11.712 21.157 14.856 ;
     RECT  21.049 16.656 21.157 17.064 ;
     RECT  20.221 20.448 21.157 22.056 ;
     RECT  20.221 23.328 21.193 23.352 ;
     RECT  20.629 24.336 21.193 24.36 ;
     RECT  20.833 2.832 21.308 9.96 ;
     RECT  21.157 11.712 21.308 17.064 ;
     RECT  20.509 19.008 21.308 19.272 ;
     RECT  21.157 20.448 21.308 22.2 ;
     RECT  21.193 23.328 21.308 24.36 ;
     RECT  21.068 25.392 21.308 27.72 ;
     RECT  20.003 30.24 21.308 30.264 ;
     RECT  20.833 31.824 21.308 32.28 ;
     RECT  18.904 34.608 21.308 34.824 ;
     RECT  20.291 36.528 21.308 36.696 ;
     RECT  20.189 39.024 21.308 39.048 ;
     RECT  20.291 40.032 21.308 40.056 ;
     RECT  21.308 2.148 21.412 41.052 ;
     RECT  21.412 2.256 21.604 40.782 ;
     RECT  21.604 33.648 21.629 33.672 ;
     RECT  21.604 39.024 21.701 40.056 ;
     RECT  21.604 22.032 21.737 22.056 ;
     RECT  21.604 2.256 21.773 5.496 ;
     RECT  21.604 7.104 21.827 9.672 ;
     RECT  21.604 26.64 21.827 28.536 ;
     RECT  21.604 16.656 21.881 17.16 ;
     RECT  21.827 26.64 21.917 28.488 ;
     RECT  21.773 3.408 21.953 5.496 ;
     RECT  21.827 9.36 22.067 9.672 ;
     RECT  21.881 16.896 22.133 17.16 ;
     RECT  22.133 17.136 22.205 17.16 ;
     RECT  21.953 4.128 22.241 5.496 ;
     RECT  21.827 7.104 22.277 8.184 ;
     RECT  21.604 12.528 22.277 13.08 ;
     RECT  21.604 14.592 22.32 14.664 ;
     RECT  21.604 37.584 22.355 37.608 ;
     RECT  21.773 2.256 22.421 2.376 ;
     RECT  21.917 27.888 22.451 28.488 ;
     RECT  21.604 29.616 22.451 29.64 ;
     RECT  21.701 39.12 22.457 40.056 ;
     RECT  22.277 13.056 22.529 13.08 ;
     RECT  21.917 26.64 22.637 26.808 ;
     RECT  21.604 31.872 22.643 32.472 ;
     RECT  21.604 30.816 22.813 30.84 ;
     RECT  21.604 35.328 22.813 35.352 ;
     RECT  21.604 36.528 22.813 36.6 ;
     RECT  22.457 39.12 22.813 39.24 ;
     RECT  22.067 9.648 22.849 9.672 ;
     RECT  22.813 35.328 22.853 36.6 ;
     RECT  22.32 14.64 22.957 14.664 ;
     RECT  22.813 30.816 22.957 30.888 ;
     RECT  21.604 18.72 22.988 19.272 ;
     RECT  22.741 17.184 23.029 17.688 ;
     RECT  22.988 18.72 23.029 19.656 ;
     RECT  22.813 39.024 23.173 39.24 ;
     RECT  23.029 17.184 23.245 20.616 ;
     RECT  22.241 4.128 23.317 5.256 ;
     RECT  22.277 7.104 23.317 7.128 ;
     RECT  22.597 33.888 23.633 33.912 ;
     RECT  23.353 11.952 23.653 11.976 ;
     RECT  23.317 6.912 23.713 7.128 ;
     RECT  22.277 8.16 23.713 8.184 ;
     RECT  21.604 23.808 23.893 23.832 ;
     RECT  22.637 26.784 23.965 26.808 ;
     RECT  22.451 27.888 23.965 28.44 ;
     RECT  22.421 2.256 24.008 2.28 ;
     RECT  23.317 4.128 24.008 5.352 ;
     RECT  23.713 6.912 24.008 8.184 ;
     RECT  22.849 9.648 24.008 10.296 ;
     RECT  23.653 11.952 24.008 12.744 ;
     RECT  22.957 14.64 24.008 14.904 ;
     RECT  23.245 16.848 24.008 20.616 ;
     RECT  23.893 23.808 24.008 25.224 ;
     RECT  23.965 26.784 24.008 28.44 ;
     RECT  23.641 29.76 24.008 29.784 ;
     RECT  22.957 30.768 24.008 30.888 ;
     RECT  23.633 33.888 24.008 34.776 ;
     RECT  22.853 35.808 24.008 36.6 ;
     RECT  23.173 38.784 24.008 39.24 ;
     RECT  24.008 2.148 24.112 41.052 ;
     RECT  24.112 2.418 24.304 40.782 ;
     RECT  24.304 24.624 24.329 25.224 ;
     RECT  24.304 16.848 24.401 19.272 ;
     RECT  24.304 23.616 24.437 23.64 ;
     RECT  24.304 11.952 24.689 15 ;
     RECT  24.401 17.088 24.833 19.272 ;
     RECT  24.304 21.648 24.833 22.536 ;
     RECT  24.304 6.816 25.013 10.872 ;
     RECT  24.833 18.192 25.013 19.032 ;
     RECT  24.304 33.024 25.021 33.672 ;
     RECT  25.013 8.352 25.043 10.872 ;
     RECT  25.043 8.352 25.057 8.52 ;
     RECT  24.304 36.288 25.085 37.128 ;
     RECT  24.304 4.272 25.091 5.592 ;
     RECT  25.043 9.648 25.091 10.872 ;
     RECT  24.833 17.088 25.091 17.208 ;
     RECT  25.013 6.816 25.121 7.224 ;
     RECT  25.013 18.672 25.235 19.032 ;
     RECT  24.304 20.592 25.297 20.616 ;
     RECT  24.329 24.624 25.32 24.648 ;
     RECT  24.304 30.816 25.337 31.368 ;
     RECT  25.32 24.624 25.409 25.08 ;
     RECT  25.34 26.448 25.427 26.472 ;
     RECT  24.833 22.176 25.441 22.536 ;
     RECT  25.297 20.592 25.445 21.096 ;
     RECT  25.121 6.816 25.481 6.888 ;
     RECT  24.689 12.48 25.573 15 ;
     RECT  25.337 31.248 25.585 31.368 ;
     RECT  25.573 12.48 25.619 15.432 ;
     RECT  25.585 31.248 25.693 31.992 ;
     RECT  25.021 33.024 25.693 33.048 ;
     RECT  25.441 22.176 25.697 22.632 ;
     RECT  25.693 31.248 25.697 33.048 ;
     RECT  24.304 27.888 25.729 27.912 ;
     RECT  25.619 12.48 25.733 13.704 ;
     RECT  25.697 31.92 25.733 33.048 ;
     RECT  25.409 25.056 25.873 25.08 ;
     RECT  25.091 17.088 26.06 17.112 ;
     RECT  25.235 18.672 26.101 18.696 ;
     RECT  26.012 1.104 26.117 1.128 ;
     RECT  24.304 29.616 26.197 29.64 ;
     RECT  26.117 0.576 26.233 1.128 ;
     RECT  26.233 0.576 26.341 1.752 ;
     RECT  25.873 25.056 26.377 25.368 ;
     RECT  25.091 4.56 26.437 5.592 ;
     RECT  25.481 6.864 26.444 6.888 ;
     RECT  25.057 8.352 26.444 8.376 ;
     RECT  25.091 9.792 26.449 10.872 ;
     RECT  26.341 0.096 26.489 1.752 ;
     RECT  25.619 14.832 26.521 15.432 ;
     RECT  26.06 17.088 26.521 17.496 ;
     RECT  26.485 34.464 26.581 34.488 ;
     RECT  26.489 0.144 26.593 1.752 ;
     RECT  25.405 2.832 26.593 2.856 ;
     RECT  26.593 0.144 26.597 2.856 ;
     RECT  25.909 23.904 26.665 23.928 ;
     RECT  26.377 25.056 26.665 25.704 ;
     RECT  26.597 0.528 26.708 2.856 ;
     RECT  26.437 4.56 26.708 5.88 ;
     RECT  26.444 6.864 26.708 8.376 ;
     RECT  26.449 9.792 26.708 11.448 ;
     RECT  25.733 12.912 26.708 13.704 ;
     RECT  26.521 14.832 26.708 17.496 ;
     RECT  26.101 18.528 26.708 18.696 ;
     RECT  25.445 20.592 26.708 20.856 ;
     RECT  25.697 22.464 26.708 22.632 ;
     RECT  26.665 23.904 26.708 25.704 ;
     RECT  25.729 27.456 26.708 27.912 ;
     RECT  26.197 28.896 26.708 29.64 ;
     RECT  25.733 31.92 26.708 32.52 ;
     RECT  26.581 33.648 26.708 34.488 ;
     RECT  26.269 36.096 26.708 36.12 ;
     RECT  25.085 37.104 26.708 37.128 ;
     RECT  24.304 39.024 26.708 39.528 ;
     RECT  26.708 0.528 26.812 41.052 ;
     RECT  26.812 0.528 27.004 40.782 ;
     RECT  27.004 0.528 27.065 6.888 ;
     RECT  27.004 22.464 27.137 24.648 ;
     RECT  27.137 22.464 27.181 24.552 ;
     RECT  27.004 20.64 27.209 20.856 ;
     RECT  27.004 27.456 27.389 30.216 ;
     RECT  27.389 27.888 27.395 30.216 ;
     RECT  27.004 33.6 27.395 36.12 ;
     RECT  27.395 33.6 27.436 34.2 ;
     RECT  27.395 35.28 27.436 35.448 ;
     RECT  27.004 25.632 27.484 26.376 ;
     RECT  27.181 23.904 27.569 24.552 ;
     RECT  27.395 28.464 27.569 30.216 ;
     RECT  27.065 0.576 27.749 6.888 ;
     RECT  27.436 33.6 27.757 33.672 ;
     RECT  27.004 31.872 27.777 32.52 ;
     RECT  27.004 11.952 27.821 13.704 ;
     RECT  27.004 37.104 27.893 37.272 ;
     RECT  27.004 15.312 27.971 18.888 ;
     RECT  27.971 16.8 28.028 18.888 ;
     RECT  27.757 33.6 28.073 33.624 ;
     RECT  28.028 16.8 28.115 19.752 ;
     RECT  28.115 16.8 28.145 18.84 ;
     RECT  27.436 35.328 28.145 35.448 ;
     RECT  27.749 1.152 28.253 5.208 ;
     RECT  27.821 11.952 28.433 12.936 ;
     RECT  27.569 23.952 28.441 24.552 ;
     RECT  27.893 37.104 28.789 37.128 ;
     RECT  28.241 0.096 28.801 0.12 ;
     RECT  27.181 22.464 28.897 22.488 ;
     RECT  27.004 9.888 28.933 9.912 ;
     RECT  28.933 9.888 29.005 10.872 ;
     RECT  28.885 0.144 29.075 0.168 ;
     RECT  28.897 22.08 29.077 22.488 ;
     RECT  27.971 15.312 29.113 15.336 ;
     RECT  27.209 20.832 29.113 20.856 ;
     RECT  29.077 22.08 29.113 22.584 ;
     RECT  27.569 28.464 29.113 28.488 ;
     RECT  28.145 16.848 29.125 16.872 ;
     RECT  29.113 20.832 29.132 22.584 ;
     RECT  28.357 8.496 29.18 8.52 ;
     RECT  29.005 9.696 29.18 10.872 ;
     RECT  28.253 1.728 29.225 5.208 ;
     RECT  29.225 1.776 29.408 5.208 ;
     RECT  27.749 6.24 29.408 6.888 ;
     RECT  29.18 8.496 29.408 10.872 ;
     RECT  28.433 12.912 29.408 12.936 ;
     RECT  29.113 14.832 29.408 15.336 ;
     RECT  29.125 16.848 29.408 16.968 ;
     RECT  28.145 18.384 29.408 18.84 ;
     RECT  29.132 20.112 29.408 22.584 ;
     RECT  28.441 24.528 29.408 24.552 ;
     RECT  27.484 26.352 29.408 26.376 ;
     RECT  29.113 27.648 29.408 28.488 ;
     RECT  27.569 29.616 29.408 30.216 ;
     RECT  27.777 31.872 29.408 31.896 ;
     RECT  28.501 33.456 29.408 33.576 ;
     RECT  28.145 35.328 29.408 35.352 ;
     RECT  28.789 36.48 29.408 37.128 ;
     RECT  27.004 39.024 29.408 39.528 ;
     RECT  29.408 1.776 29.512 41.052 ;
     RECT  29.512 1.776 29.704 40.782 ;
     RECT  29.704 3.408 29.765 3.672 ;
     RECT  29.704 1.776 29.873 2.328 ;
     RECT  29.765 3.408 30.053 3.432 ;
     RECT  29.704 39.024 30.769 39.432 ;
     RECT  30.769 39.024 32.321 39.12 ;
     RECT  30.769 39.12 32.316 39.144 ;
     RECT  30.769 39.144 32.321 39.216 ;
     RECT  30.769 39.216 32.316 39.24 ;
     RECT  30.769 39.24 32.321 39.312 ;
     RECT  30.769 39.312 32.316 39.336 ;
     RECT  30.769 39.336 32.321 39.408 ;
     RECT  30.769 39.408 32.316 39.432 ;
     RECT  30.769 39.432 32.321 39.504 ;
     RECT  30.769 39.504 32.316 39.528 ;
     RECT  30.769 39.528 32.321 39.6 ;
     RECT  30.769 39.6 32.316 39.624 ;
     RECT  32.321 39.144 32.364 39.216 ;
     RECT  32.321 39.24 32.364 39.312 ;
     RECT  32.321 39.336 32.364 39.408 ;
     RECT  32.321 39.432 32.364 39.504 ;
     RECT  32.321 39.528 32.364 39.6 ;
    LAYER M5 ;
     RECT  10.728 0.016 10.8 0.084 ;
     RECT  10.824 0.016 10.896 0.084 ;
     RECT  10.92 0.016 10.992 0.084 ;
     RECT  11.016 0.016 11.088 0.084 ;
     RECT  11.112 0.016 11.184 0.084 ;
     RECT  11.208 0.016 11.28 0.084 ;
     RECT  11.304 0.016 11.376 0.084 ;
     RECT  10.704 0.084 11.4 0.085 ;
     RECT  26.088 0.016 26.16 0.084 ;
     RECT  26.184 0.016 26.256 0.084 ;
     RECT  26.28 0.016 26.352 0.084 ;
     RECT  26.376 0.016 26.448 0.084 ;
     RECT  26.472 0.016 26.544 0.084 ;
     RECT  26.568 0.016 26.64 0.084 ;
     RECT  26.664 0.016 26.736 0.084 ;
     RECT  26.76 0.016 26.832 0.084 ;
     RECT  26.856 0.016 26.928 0.084 ;
     RECT  26.952 0.016 27.024 0.084 ;
     RECT  27.048 0.016 27.12 0.084 ;
     RECT  27.144 0.016 27.216 0.084 ;
     RECT  27.24 0.016 27.312 0.084 ;
     RECT  27.336 0.016 27.408 0.084 ;
     RECT  27.432 0.016 27.504 0.084 ;
     RECT  27.528 0.016 27.6 0.084 ;
     RECT  27.624 0.016 27.696 0.084 ;
     RECT  27.72 0.016 27.792 0.084 ;
     RECT  27.816 0.016 27.888 0.084 ;
     RECT  27.912 0.016 27.984 0.084 ;
     RECT  28.008 0.016 28.08 0.084 ;
     RECT  28.104 0.016 28.176 0.084 ;
     RECT  28.2 0.016 28.272 0.084 ;
     RECT  28.296 0.016 28.368 0.084 ;
     RECT  28.392 0.016 28.464 0.084 ;
     RECT  28.488 0.016 28.56 0.084 ;
     RECT  28.584 0.016 28.656 0.084 ;
     RECT  28.68 0.016 28.752 0.084 ;
     RECT  28.776 0.016 28.848 0.084 ;
     RECT  28.872 0.016 28.944 0.084 ;
     RECT  28.968 0.016 29.04 0.084 ;
     RECT  26.064 0.084 29.064 0.179 ;
     RECT  26.064 0.179 28.968 1.139 ;
     RECT  26.256 1.139 28.968 1.763 ;
     RECT  7.68 2.053 7.704 2.137 ;
     RECT  26.7 1.763 28.968 2.137 ;
     RECT  2.4 2.137 2.52 2.151 ;
     RECT  5.1 2.137 5.22 2.151 ;
     RECT  7.68 2.137 7.92 2.151 ;
     RECT  13.2 2.137 13.32 2.151 ;
     RECT  15.9 2.137 16.02 2.151 ;
     RECT  18.6 2.137 18.72 2.151 ;
     RECT  21.3 2.137 21.42 2.151 ;
     RECT  24 2.137 24.12 2.151 ;
     RECT  26.7 2.137 29.52 2.151 ;
     RECT  15.9 2.151 16.212 2.245 ;
     RECT  10.368 0.085 11.4 2.291 ;
     RECT  10.368 2.291 11.112 2.773 ;
     RECT  5.1 2.151 5.412 2.821 ;
     RECT  10.272 2.773 11.112 3.109 ;
     RECT  4.704 2.821 5.412 3.443 ;
     RECT  26.7 2.151 29.712 3.443 ;
     RECT  27.984 3.443 29.712 3.683 ;
     RECT  21.3 2.151 21.612 3.685 ;
     RECT  9.792 3.109 11.112 3.925 ;
     RECT  18.6 2.151 18.912 3.925 ;
     RECT  24 2.151 24.312 4.261 ;
     RECT  15.9 2.245 17.16 4.357 ;
     RECT  18.432 3.925 18.912 4.357 ;
     RECT  26.7 3.443 27.012 4.501 ;
     RECT  26.7 4.501 27.912 4.693 ;
     RECT  28.896 3.683 29.712 4.693 ;
     RECT  9.792 3.925 12.024 4.835 ;
     RECT  13.2 2.151 13.512 4.837 ;
     RECT  15.9 4.357 18.912 4.979 ;
     RECT  7.68 2.151 8.112 5.029 ;
     RECT  21.3 3.685 21.912 5.029 ;
     RECT  17.472 4.979 18.912 5.077 ;
     RECT  24 4.261 25.08 5.317 ;
     RECT  20.64 5.029 21.912 5.507 ;
     RECT  23.376 5.317 25.08 5.557 ;
     RECT  26.7 4.693 29.712 5.557 ;
     RECT  17.472 5.077 19.656 5.699 ;
     RECT  9.792 4.835 11.112 5.797 ;
     RECT  12.288 4.837 13.512 5.797 ;
     RECT  26.448 5.557 29.712 6.275 ;
     RECT  7.488 5.029 8.568 6.323 ;
     RECT  21.072 5.507 21.912 6.323 ;
     RECT  17.808 5.699 19.656 6.515 ;
     RECT  28.752 6.275 29.712 6.563 ;
     RECT  5.1 3.443 5.412 6.661 ;
     RECT  2.4 2.151 2.712 6.805 ;
     RECT  7.8 6.323 8.568 6.851 ;
     RECT  26.448 6.275 27.384 6.899 ;
     RECT  9.792 5.797 13.512 7.189 ;
     RECT  17.184 6.805 17.208 7.619 ;
     RECT  18.6 6.515 19.656 7.909 ;
     RECT  9.696 7.189 13.512 8.195 ;
     RECT  23.376 5.557 25.224 8.341 ;
     RECT  26.448 6.899 27.012 8.341 ;
     RECT  5.1 6.661 5.784 8.437 ;
     RECT  7.8 6.851 8.112 8.485 ;
     RECT  29.04 6.563 29.712 8.485 ;
     RECT  18.24 7.909 19.656 8.579 ;
     RECT  14.784 6.805 14.808 8.629 ;
     RECT  14.496 8.629 14.808 8.675 ;
     RECT  5.1 8.437 6.408 9.349 ;
     RECT  21.3 6.323 21.912 9.349 ;
     RECT  7.392 8.485 8.112 9.731 ;
     RECT  2.4 6.805 2.808 9.779 ;
     RECT  14.496 8.675 14.52 9.923 ;
     RECT  4.176 9.349 6.408 9.971 ;
     RECT  18.48 8.579 19.656 10.069 ;
     RECT  18.432 10.069 19.656 11.027 ;
     RECT  4.176 9.971 5.976 11.219 ;
     RECT  12.288 8.195 13.512 11.365 ;
     RECT  2.4 9.779 2.712 11.941 ;
     RECT  4.176 11.219 5.544 11.941 ;
     RECT  7.8 9.731 8.112 11.941 ;
     RECT  15.9 4.979 16.212 11.941 ;
     RECT  2.4 11.941 5.544 12.517 ;
     RECT  21.3 9.349 22.056 12.517 ;
     RECT  7.056 11.941 8.112 12.755 ;
     RECT  21.12 12.517 22.056 13.045 ;
     RECT  18.48 11.027 19.656 13.285 ;
     RECT  21.12 13.045 22.248 13.285 ;
     RECT  9.696 8.195 10.812 13.333 ;
     RECT  15.9 11.941 16.824 13.813 ;
     RECT  18.48 13.285 22.248 13.813 ;
     RECT  12.288 11.365 14.28 14.053 ;
     RECT  12.288 14.053 14.568 14.099 ;
     RECT  15.9 13.813 22.248 14.197 ;
     RECT  14.544 14.099 14.568 14.389 ;
     RECT  15.744 14.197 22.248 14.389 ;
     RECT  7.8 12.755 8.112 14.485 ;
     RECT  9.552 13.333 10.812 14.531 ;
     RECT  14.544 14.389 22.248 14.627 ;
     RECT  14.544 14.627 22.056 14.867 ;
     RECT  7.8 14.485 8.28 15.107 ;
     RECT  12.288 14.099 13.512 15.301 ;
     RECT  14.544 14.867 14.568 15.301 ;
     RECT  23.376 8.341 27.012 15.301 ;
     RECT  28.368 8.485 29.712 15.301 ;
     RECT  12.288 15.301 14.568 15.829 ;
     RECT  15.744 14.867 16.824 15.829 ;
     RECT  12.288 15.829 16.824 16.117 ;
     RECT  18.6 14.867 19.656 16.165 ;
     RECT  11.808 16.117 16.824 16.499 ;
     RECT  15.216 16.499 16.824 16.739 ;
     RECT  23.376 15.301 29.712 16.835 ;
     RECT  15.312 16.739 16.824 17.077 ;
     RECT  18.048 16.165 19.656 17.077 ;
     RECT  21.12 14.867 22.056 17.173 ;
     RECT  23.376 16.835 27.012 17.173 ;
     RECT  15.312 17.077 19.656 17.219 ;
     RECT  21.12 17.173 27.012 17.699 ;
     RECT  18.6 17.219 19.656 18.133 ;
     RECT  28.368 16.835 29.712 18.373 ;
     RECT  23.04 17.699 27.012 18.563 ;
     RECT  2.4 12.517 5.64 18.565 ;
     RECT  26.496 18.563 27.012 18.661 ;
     RECT  28.08 18.373 29.712 18.661 ;
     RECT  11.808 16.499 14.04 18.757 ;
     RECT  11.808 18.757 14.136 18.803 ;
     RECT  26.496 18.661 29.712 18.899 ;
     RECT  15.312 17.219 16.92 18.947 ;
     RECT  12.336 18.803 14.136 18.995 ;
     RECT  18.6 18.133 19.944 18.997 ;
     RECT  23.04 18.563 25.224 19.043 ;
     RECT  2.4 18.565 6.264 19.571 ;
     RECT  9.696 14.531 10.812 19.909 ;
     RECT  18.192 18.997 19.944 19.909 ;
     RECT  12.384 18.995 14.136 20.003 ;
     RECT  18.096 19.909 19.944 20.053 ;
     RECT  9.696 19.909 11.016 20.435 ;
     RECT  18 20.053 19.944 20.483 ;
     RECT  7.8 15.107 8.112 20.485 ;
     RECT  23.04 19.043 24.84 20.627 ;
     RECT  28.08 18.899 29.712 20.867 ;
     RECT  7.8 20.485 8.712 20.869 ;
     RECT  9.696 20.435 10.812 20.869 ;
     RECT  7.8 20.869 10.812 21.107 ;
     RECT  9.408 21.107 10.812 21.155 ;
     RECT  28.368 20.867 29.712 21.683 ;
     RECT  26.496 18.899 27.012 22.453 ;
     RECT  26.496 22.453 27.144 22.979 ;
     RECT  21.12 17.699 22.056 23.317 ;
     RECT  9.408 21.155 9.432 23.701 ;
     RECT  28.368 21.683 28.392 23.987 ;
     RECT  12 22.453 12.024 24.131 ;
     RECT  13.2 20.003 14.136 24.229 ;
     RECT  15.312 18.947 16.824 24.229 ;
     RECT  20.64 23.317 22.056 24.371 ;
     RECT  7.8 21.107 8.112 24.469 ;
     RECT  9.12 23.701 9.432 24.469 ;
     RECT  13.2 24.229 16.824 24.469 ;
     RECT  18 20.483 19.656 24.469 ;
     RECT  23.616 20.627 24.84 25.045 ;
     RECT  23.616 25.045 25.416 25.333 ;
     RECT  26.496 22.979 27.012 25.333 ;
     RECT  21.12 24.371 22.056 25.427 ;
     RECT  7.8 24.469 9.432 25.573 ;
     RECT  10.5 21.155 10.812 25.573 ;
     RECT  23.616 25.333 27.012 25.621 ;
     RECT  7.8 25.573 10.812 26.339 ;
     RECT  23.616 25.621 27.432 26.387 ;
     RECT  23.616 26.387 27.012 26.483 ;
     RECT  2.4 19.571 5.64 26.917 ;
     RECT  13.2 24.469 19.656 27.301 ;
     RECT  2.4 26.917 5.688 27.733 ;
     RECT  7.8 26.339 9.432 27.829 ;
     RECT  10.5 26.339 10.812 27.829 ;
     RECT  26.208 26.483 27.012 27.877 ;
     RECT  7.8 27.829 10.812 28.211 ;
     RECT  21.3 25.427 22.056 28.453 ;
     RECT  26.208 27.877 27.384 28.499 ;
     RECT  12.384 27.301 19.656 28.547 ;
     RECT  26.208 28.499 27.012 28.931 ;
     RECT  13.2 28.547 19.656 29.267 ;
     RECT  7.8 28.211 9.432 30.133 ;
     RECT  10.5 28.211 10.812 30.133 ;
     RECT  19.968 30.229 19.992 30.803 ;
     RECT  21.3 28.453 22.44 30.851 ;
     RECT  7.8 30.133 10.812 30.899 ;
     RECT  23.616 26.483 24.84 31.379 ;
     RECT  13.2 29.267 18.912 31.381 ;
     RECT  7.8 30.899 9.432 31.955 ;
     RECT  26.544 28.931 27.012 31.955 ;
     RECT  2.4 27.733 5.928 32.437 ;
     RECT  26.592 31.955 27.012 32.485 ;
     RECT  23.616 31.379 24.312 33.013 ;
     RECT  13.104 31.381 18.912 33.251 ;
     RECT  23.616 33.013 24.984 33.683 ;
     RECT  26.592 32.485 27.72 33.683 ;
     RECT  22.608 31.861 22.632 33.923 ;
     RECT  21.3 30.851 21.612 35.317 ;
     RECT  29.4 21.683 29.712 35.317 ;
     RECT  23.616 33.683 24.312 35.843 ;
     RECT  23.664 35.843 24.312 36.227 ;
     RECT  13.2 33.251 18.912 36.659 ;
     RECT  29.136 35.317 29.712 36.755 ;
     RECT  13.2 36.659 16.632 37.045 ;
     RECT  26.7 33.683 27.384 37.283 ;
     RECT  20.256 36.133 20.28 37.573 ;
     RECT  17.616 36.659 18.912 37.619 ;
     RECT  12.528 37.045 16.632 37.667 ;
     RECT  20.016 37.573 20.28 38.675 ;
     RECT  18 37.619 18.912 39.059 ;
     RECT  21.3 35.317 22.344 39.251 ;
     RECT  18.336 39.059 18.912 39.877 ;
     RECT  20.256 38.675 20.28 40.307 ;
     RECT  13.2 37.667 16.632 40.453 ;
     RECT  2.4 32.437 6.216 40.501 ;
     RECT  13.2 40.453 17.352 40.549 ;
     RECT  18.336 39.877 19.272 40.549 ;
     RECT  13.2 40.549 19.272 40.933 ;
     RECT  7.8 31.955 8.112 41.049 ;
     RECT  10.5 30.899 10.812 41.049 ;
     RECT  21.3 39.251 21.612 41.049 ;
     RECT  24 36.227 24.312 41.049 ;
     RECT  26.7 37.283 27.012 41.049 ;
     RECT  29.4 36.755 29.712 41.049 ;
     RECT  2.4 40.501 6.312 41.063 ;
     RECT  7.8 41.049 7.92 41.063 ;
     RECT  10.5 41.049 10.62 41.063 ;
     RECT  13.2 40.933 19.368 41.063 ;
     RECT  21.3 41.049 21.42 41.063 ;
     RECT  24 41.049 24.12 41.063 ;
     RECT  26.7 41.049 26.82 41.063 ;
     RECT  29.4 41.049 29.52 41.063 ;
     RECT  3.168 41.063 6.312 43.091 ;
     RECT  9.408 31.955 9.432 43.139 ;
     RECT  3.312 43.091 6.312 43.116 ;
     RECT  3.336 43.116 3.408 43.152 ;
     RECT  3.432 43.116 3.504 43.152 ;
     RECT  3.528 43.116 3.6 43.152 ;
     RECT  3.624 43.116 3.696 43.152 ;
     RECT  3.72 43.116 3.792 43.152 ;
     RECT  3.816 43.116 3.888 43.152 ;
     RECT  3.912 43.116 3.984 43.152 ;
     RECT  4.008 43.116 4.08 43.152 ;
     RECT  4.104 43.116 4.176 43.152 ;
     RECT  4.2 43.116 4.272 43.152 ;
     RECT  4.296 43.116 4.368 43.152 ;
     RECT  4.392 43.116 4.464 43.152 ;
     RECT  4.488 43.116 4.56 43.152 ;
     RECT  4.584 43.116 4.656 43.152 ;
     RECT  4.68 43.116 4.752 43.152 ;
     RECT  4.776 43.116 4.848 43.152 ;
     RECT  4.872 43.116 4.944 43.152 ;
     RECT  4.968 43.116 5.04 43.152 ;
     RECT  5.064 43.116 5.136 43.152 ;
     RECT  5.16 43.116 5.232 43.152 ;
     RECT  5.256 43.116 5.328 43.152 ;
     RECT  5.352 43.116 5.424 43.152 ;
     RECT  5.448 43.116 5.52 43.152 ;
     RECT  5.544 43.116 5.616 43.152 ;
     RECT  5.64 43.116 5.712 43.152 ;
     RECT  5.736 43.116 5.808 43.152 ;
     RECT  5.832 43.116 5.904 43.152 ;
     RECT  5.928 43.116 6 43.152 ;
     RECT  6.024 43.116 6.096 43.152 ;
     RECT  6.12 43.116 6.192 43.152 ;
     RECT  6.216 43.116 6.288 43.152 ;
     RECT  13.296 41.063 19.368 43.116 ;
     RECT  13.32 43.116 13.392 43.152 ;
     RECT  13.416 43.116 13.488 43.152 ;
     RECT  13.512 43.116 13.584 43.152 ;
     RECT  13.608 43.116 13.68 43.152 ;
     RECT  13.704 43.116 13.776 43.152 ;
     RECT  13.8 43.116 13.872 43.152 ;
     RECT  13.896 43.116 13.968 43.152 ;
     RECT  13.992 43.116 14.064 43.152 ;
     RECT  14.088 43.116 14.16 43.152 ;
     RECT  14.184 43.116 14.256 43.152 ;
     RECT  14.28 43.116 14.352 43.152 ;
     RECT  14.376 43.116 14.448 43.152 ;
     RECT  14.472 43.116 14.544 43.152 ;
     RECT  14.568 43.116 14.64 43.152 ;
     RECT  14.664 43.116 14.736 43.152 ;
     RECT  14.76 43.116 14.832 43.152 ;
     RECT  14.856 43.116 14.928 43.152 ;
     RECT  14.952 43.116 15.024 43.152 ;
     RECT  15.048 43.116 15.12 43.152 ;
     RECT  15.144 43.116 15.216 43.152 ;
     RECT  15.24 43.116 15.312 43.152 ;
     RECT  15.336 43.116 15.408 43.152 ;
     RECT  15.432 43.116 15.504 43.152 ;
     RECT  15.528 43.116 15.6 43.152 ;
     RECT  15.624 43.116 15.696 43.152 ;
     RECT  15.72 43.116 15.792 43.152 ;
     RECT  15.816 43.116 15.888 43.152 ;
     RECT  15.912 43.116 15.984 43.152 ;
     RECT  16.008 43.116 16.08 43.152 ;
     RECT  16.104 43.116 16.176 43.152 ;
     RECT  16.2 43.116 16.272 43.152 ;
     RECT  16.296 43.116 16.368 43.152 ;
     RECT  16.392 43.116 16.464 43.152 ;
     RECT  16.488 43.116 16.56 43.152 ;
     RECT  16.584 43.116 16.656 43.152 ;
     RECT  16.68 43.116 16.752 43.152 ;
     RECT  16.776 43.116 16.848 43.152 ;
     RECT  16.872 43.116 16.944 43.152 ;
     RECT  16.968 43.116 17.04 43.152 ;
     RECT  17.064 43.116 17.136 43.152 ;
     RECT  17.16 43.116 17.232 43.152 ;
     RECT  17.256 43.116 17.328 43.152 ;
     RECT  17.352 43.116 17.424 43.152 ;
     RECT  17.448 43.116 17.52 43.152 ;
     RECT  17.544 43.116 17.616 43.152 ;
     RECT  17.64 43.116 17.712 43.152 ;
     RECT  17.736 43.116 17.808 43.152 ;
     RECT  17.832 43.116 17.904 43.152 ;
     RECT  17.928 43.116 18 43.152 ;
     RECT  18.024 43.116 18.096 43.152 ;
     RECT  18.12 43.116 18.192 43.152 ;
     RECT  18.216 43.116 18.288 43.152 ;
     RECT  18.312 43.116 18.384 43.152 ;
     RECT  18.408 43.116 18.48 43.152 ;
     RECT  18.504 43.116 18.576 43.152 ;
     RECT  18.6 43.116 18.672 43.152 ;
     RECT  18.696 43.116 18.768 43.152 ;
     RECT  18.792 43.116 18.864 43.152 ;
     RECT  18.888 43.116 18.96 43.152 ;
     RECT  18.984 43.116 19.056 43.152 ;
     RECT  19.08 43.116 19.152 43.152 ;
     RECT  19.176 43.116 19.248 43.152 ;
     RECT  19.272 43.116 19.344 43.152 ;
     RECT  5.664 43.152 5.688 43.187 ;
     RECT  17.16 2.245 18.6 3.925 ;
     RECT  27.012 3.443 27.984 3.683 ;
     RECT  27.012 3.683 28.896 4.501 ;
     RECT  12.024 3.925 13.2 4.835 ;
     RECT  17.16 3.925 18.432 4.357 ;
     RECT  27.912 4.501 28.896 4.693 ;
     RECT  11.112 4.835 13.2 4.837 ;
     RECT  11.112 4.837 12.288 5.797 ;
     RECT  16.212 4.979 17.472 5.699 ;
     RECT  8.568 5.029 9.792 6.851 ;
     RECT  19.656 5.077 20.64 5.507 ;
     RECT  21.912 5.317 23.376 9.349 ;
     RECT  19.656 5.507 21.072 6.323 ;
     RECT  25.224 5.557 26.448 8.341 ;
     RECT  16.212 5.699 17.808 6.515 ;
     RECT  27.384 6.275 28.752 6.563 ;
     RECT  16.212 6.515 18.6 6.805 ;
     RECT  13.512 6.805 14.784 8.629 ;
     RECT  14.808 6.805 15.9 8.675 ;
     RECT  16.212 6.805 17.184 7.619 ;
     RECT  17.208 6.805 18.6 7.619 ;
     RECT  9.696 6.851 9.792 7.189 ;
     RECT  18.24 7.619 18.6 7.909 ;
     RECT  10.812 8.195 12.288 16.117 ;
     RECT  6.408 8.437 7.8 8.485 ;
     RECT  6.408 8.485 7.392 9.731 ;
     RECT  27.012 8.485 28.368 15.301 ;
     RECT  18.432 8.579 18.48 10.069 ;
     RECT  13.512 8.629 14.496 9.923 ;
     RECT  14.52 8.675 15.9 9.923 ;
     RECT  2.808 9.349 4.176 9.779 ;
     RECT  22.056 9.349 23.376 13.045 ;
     RECT  6.408 9.731 7.8 9.971 ;
     RECT  2.712 9.779 4.176 11.941 ;
     RECT  13.512 9.923 14.28 11.365 ;
     RECT  5.544 11.219 5.976 11.941 ;
     RECT  5.544 11.941 7.056 12.517 ;
     RECT  5.64 12.517 7.056 12.755 ;
     RECT  19.656 12.517 21.12 13.285 ;
     RECT  22.248 13.045 23.376 14.627 ;
     RECT  8.112 13.333 9.552 14.485 ;
     RECT  14.568 14.053 15.9 14.197 ;
     RECT  13.512 14.099 14.544 15.301 ;
     RECT  14.568 14.197 15.744 14.389 ;
     RECT  8.28 14.485 9.552 14.531 ;
     RECT  8.28 14.531 9.696 15.107 ;
     RECT  22.056 14.627 23.376 17.173 ;
     RECT  14.568 14.867 15.744 15.829 ;
     RECT  16.824 14.867 18.6 16.165 ;
     RECT  19.656 14.867 21.12 18.133 ;
     RECT  10.812 16.117 11.808 18.803 ;
     RECT  16.824 16.165 18.048 17.077 ;
     RECT  14.04 16.499 15.216 16.739 ;
     RECT  14.04 16.739 15.312 18.757 ;
     RECT  27.012 16.835 28.368 18.373 ;
     RECT  22.056 17.699 23.04 20.627 ;
     RECT  19.944 18.133 21.12 20.483 ;
     RECT  27.012 18.373 28.08 18.661 ;
     RECT  25.224 18.563 26.496 19.043 ;
     RECT  14.136 18.757 15.312 24.229 ;
     RECT  10.812 18.803 12.336 18.995 ;
     RECT  27.012 18.899 28.08 20.867 ;
     RECT  16.824 18.947 16.92 18.997 ;
     RECT  10.812 18.995 12.384 19.909 ;
     RECT  16.824 18.997 18.192 19.909 ;
     RECT  11.016 19.909 12.384 20.003 ;
     RECT  16.824 19.909 18.096 20.053 ;
     RECT  16.824 20.053 18 24.469 ;
     RECT  19.656 20.483 21.12 23.317 ;
     RECT  8.712 20.485 9.696 20.869 ;
     RECT  27.012 20.867 28.368 22.453 ;
     RECT  8.112 21.107 9.408 23.701 ;
     RECT  9.432 21.155 10.5 25.573 ;
     RECT  28.392 21.683 29.4 23.987 ;
     RECT  10.812 22.453 12 24.131 ;
     RECT  12.024 22.453 13.2 24.131 ;
     RECT  27.144 22.453 28.368 22.979 ;
     RECT  27.012 22.979 28.368 23.987 ;
     RECT  19.656 23.317 20.64 24.371 ;
     RECT  8.112 23.701 9.12 24.469 ;
     RECT  19.656 24.371 21.12 25.427 ;
     RECT  25.416 25.045 26.496 25.333 ;
     RECT  9.432 26.339 10.5 27.829 ;
     RECT  27.012 26.387 27.384 27.877 ;
     RECT  24.84 26.483 26.208 28.931 ;
     RECT  9.432 28.211 10.5 30.133 ;
     RECT  22.44 28.453 23.616 30.851 ;
     RECT  18.912 29.267 19.656 30.229 ;
     RECT  18.912 30.229 19.968 30.803 ;
     RECT  19.992 30.229 21.3 30.803 ;
     RECT  21.612 30.851 23.616 31.861 ;
     RECT  9.432 30.899 10.5 41.063 ;
     RECT  21.612 31.861 22.608 33.923 ;
     RECT  22.632 31.861 23.616 33.923 ;
     RECT  8.112 31.955 9.408 41.049 ;
     RECT  21.612 33.923 23.616 35.317 ;
     RECT  22.344 35.317 23.616 35.843 ;
     RECT  22.344 35.843 23.664 36.227 ;
     RECT  18.912 36.133 20.256 37.573 ;
     RECT  20.28 36.133 21.3 40.307 ;
     RECT  16.632 36.659 17.616 37.619 ;
     RECT  18.912 37.573 20.016 38.675 ;
     RECT  16.632 37.619 18 39.059 ;
     RECT  18.912 38.675 20.256 39.877 ;
     RECT  16.632 39.059 18.336 40.453 ;
     RECT  19.272 39.877 20.256 40.307 ;
     RECT  19.272 40.307 19.368 40.933 ;
     RECT  17.352 40.453 18.336 40.549 ;
     RECT  6.312 40.501 7.8 41.063 ;
     RECT  7.92 41.049 9.408 41.063 ;
  END
END hbfd_land_136_NS
END LIBRARY
